VERSION 5.7 ;
BUSBITCHARS "[]" ;
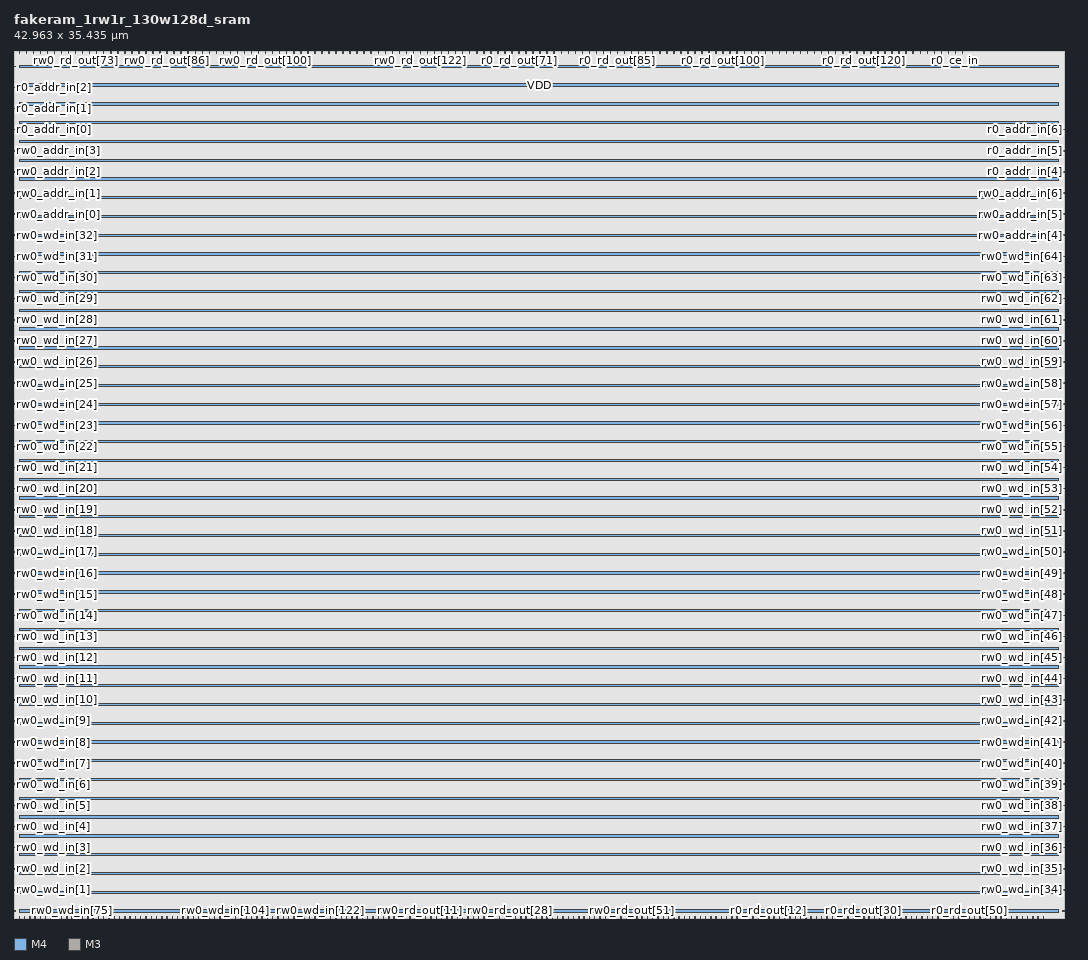
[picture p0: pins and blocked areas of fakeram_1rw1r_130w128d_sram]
MACRO fakeram_1rw1r_130w128d_sram
  FOREIGN fakeram_1rw1r_130w128d_sram 0 0 ;
  SYMMETRY X Y R90 ;
  SIZE 42.963 BY 35.435 ;
  CLASS BLOCK ;
  PIN rw0_wd_in[0]
    DIRECTION INPUT ;
    USE SIGNAL ;
    SHAPE ABUTMENT ;
    PORT
      LAYER M4 ;
      RECT 0.000 0.276 0.072 0.300 ;
    END
  END rw0_wd_in[0]
  PIN rw0_wd_in[1]
    DIRECTION INPUT ;
    USE SIGNAL ;
    SHAPE ABUTMENT ;
    PORT
      LAYER M4 ;
      RECT 0.000 1.140 0.072 1.164 ;
    END
  END rw0_wd_in[1]
  PIN rw0_wd_in[2]
    DIRECTION INPUT ;
    USE SIGNAL ;
    SHAPE ABUTMENT ;
    PORT
      LAYER M4 ;
      RECT 0.000 2.004 0.072 2.028 ;
    END
  END rw0_wd_in[2]
  PIN rw0_wd_in[3]
    DIRECTION INPUT ;
    USE SIGNAL ;
    SHAPE ABUTMENT ;
    PORT
      LAYER M4 ;
      RECT 0.000 2.868 0.072 2.892 ;
    END
  END rw0_wd_in[3]
  PIN rw0_wd_in[4]
    DIRECTION INPUT ;
    USE SIGNAL ;
    SHAPE ABUTMENT ;
    PORT
      LAYER M4 ;
      RECT 0.000 3.732 0.072 3.756 ;
    END
  END rw0_wd_in[4]
  PIN rw0_wd_in[5]
    DIRECTION INPUT ;
    USE SIGNAL ;
    SHAPE ABUTMENT ;
    PORT
      LAYER M4 ;
      RECT 0.000 4.596 0.072 4.620 ;
    END
  END rw0_wd_in[5]
  PIN rw0_wd_in[6]
    DIRECTION INPUT ;
    USE SIGNAL ;
    SHAPE ABUTMENT ;
    PORT
      LAYER M4 ;
      RECT 0.000 5.460 0.072 5.484 ;
    END
  END rw0_wd_in[6]
  PIN rw0_wd_in[7]
    DIRECTION INPUT ;
    USE SIGNAL ;
    SHAPE ABUTMENT ;
    PORT
      LAYER M4 ;
      RECT 0.000 6.324 0.072 6.348 ;
    END
  END rw0_wd_in[7]
  PIN rw0_wd_in[8]
    DIRECTION INPUT ;
    USE SIGNAL ;
    SHAPE ABUTMENT ;
    PORT
      LAYER M4 ;
      RECT 0.000 7.188 0.072 7.212 ;
    END
  END rw0_wd_in[8]
  PIN rw0_wd_in[9]
    DIRECTION INPUT ;
    USE SIGNAL ;
    SHAPE ABUTMENT ;
    PORT
      LAYER M4 ;
      RECT 0.000 8.052 0.072 8.076 ;
    END
  END rw0_wd_in[9]
  PIN rw0_wd_in[10]
    DIRECTION INPUT ;
    USE SIGNAL ;
    SHAPE ABUTMENT ;
    PORT
      LAYER M4 ;
      RECT 0.000 8.916 0.072 8.940 ;
    END
  END rw0_wd_in[10]
  PIN rw0_wd_in[11]
    DIRECTION INPUT ;
    USE SIGNAL ;
    SHAPE ABUTMENT ;
    PORT
      LAYER M4 ;
      RECT 0.000 9.780 0.072 9.804 ;
    END
  END rw0_wd_in[11]
  PIN rw0_wd_in[12]
    DIRECTION INPUT ;
    USE SIGNAL ;
    SHAPE ABUTMENT ;
    PORT
      LAYER M4 ;
      RECT 0.000 10.644 0.072 10.668 ;
    END
  END rw0_wd_in[12]
  PIN rw0_wd_in[13]
    DIRECTION INPUT ;
    USE SIGNAL ;
    SHAPE ABUTMENT ;
    PORT
      LAYER M4 ;
      RECT 0.000 11.508 0.072 11.532 ;
    END
  END rw0_wd_in[13]
  PIN rw0_wd_in[14]
    DIRECTION INPUT ;
    USE SIGNAL ;
    SHAPE ABUTMENT ;
    PORT
      LAYER M4 ;
      RECT 0.000 12.372 0.072 12.396 ;
    END
  END rw0_wd_in[14]
  PIN rw0_wd_in[15]
    DIRECTION INPUT ;
    USE SIGNAL ;
    SHAPE ABUTMENT ;
    PORT
      LAYER M4 ;
      RECT 0.000 13.236 0.072 13.260 ;
    END
  END rw0_wd_in[15]
  PIN rw0_wd_in[16]
    DIRECTION INPUT ;
    USE SIGNAL ;
    SHAPE ABUTMENT ;
    PORT
      LAYER M4 ;
      RECT 0.000 14.100 0.072 14.124 ;
    END
  END rw0_wd_in[16]
  PIN rw0_wd_in[17]
    DIRECTION INPUT ;
    USE SIGNAL ;
    SHAPE ABUTMENT ;
    PORT
      LAYER M4 ;
      RECT 0.000 14.964 0.072 14.988 ;
    END
  END rw0_wd_in[17]
  PIN rw0_wd_in[18]
    DIRECTION INPUT ;
    USE SIGNAL ;
    SHAPE ABUTMENT ;
    PORT
      LAYER M4 ;
      RECT 0.000 15.828 0.072 15.852 ;
    END
  END rw0_wd_in[18]
  PIN rw0_wd_in[19]
    DIRECTION INPUT ;
    USE SIGNAL ;
    SHAPE ABUTMENT ;
    PORT
      LAYER M4 ;
      RECT 0.000 16.692 0.072 16.716 ;
    END
  END rw0_wd_in[19]
  PIN rw0_wd_in[20]
    DIRECTION INPUT ;
    USE SIGNAL ;
    SHAPE ABUTMENT ;
    PORT
      LAYER M4 ;
      RECT 0.000 17.556 0.072 17.580 ;
    END
  END rw0_wd_in[20]
  PIN rw0_wd_in[21]
    DIRECTION INPUT ;
    USE SIGNAL ;
    SHAPE ABUTMENT ;
    PORT
      LAYER M4 ;
      RECT 0.000 18.420 0.072 18.444 ;
    END
  END rw0_wd_in[21]
  PIN rw0_wd_in[22]
    DIRECTION INPUT ;
    USE SIGNAL ;
    SHAPE ABUTMENT ;
    PORT
      LAYER M4 ;
      RECT 0.000 19.284 0.072 19.308 ;
    END
  END rw0_wd_in[22]
  PIN rw0_wd_in[23]
    DIRECTION INPUT ;
    USE SIGNAL ;
    SHAPE ABUTMENT ;
    PORT
      LAYER M4 ;
      RECT 0.000 20.148 0.072 20.172 ;
    END
  END rw0_wd_in[23]
  PIN rw0_wd_in[24]
    DIRECTION INPUT ;
    USE SIGNAL ;
    SHAPE ABUTMENT ;
    PORT
      LAYER M4 ;
      RECT 0.000 21.012 0.072 21.036 ;
    END
  END rw0_wd_in[24]
  PIN rw0_wd_in[25]
    DIRECTION INPUT ;
    USE SIGNAL ;
    SHAPE ABUTMENT ;
    PORT
      LAYER M4 ;
      RECT 0.000 21.876 0.072 21.900 ;
    END
  END rw0_wd_in[25]
  PIN rw0_wd_in[26]
    DIRECTION INPUT ;
    USE SIGNAL ;
    SHAPE ABUTMENT ;
    PORT
      LAYER M4 ;
      RECT 0.000 22.740 0.072 22.764 ;
    END
  END rw0_wd_in[26]
  PIN rw0_wd_in[27]
    DIRECTION INPUT ;
    USE SIGNAL ;
    SHAPE ABUTMENT ;
    PORT
      LAYER M4 ;
      RECT 0.000 23.604 0.072 23.628 ;
    END
  END rw0_wd_in[27]
  PIN rw0_wd_in[28]
    DIRECTION INPUT ;
    USE SIGNAL ;
    SHAPE ABUTMENT ;
    PORT
      LAYER M4 ;
      RECT 0.000 24.468 0.072 24.492 ;
    END
  END rw0_wd_in[28]
  PIN rw0_wd_in[29]
    DIRECTION INPUT ;
    USE SIGNAL ;
    SHAPE ABUTMENT ;
    PORT
      LAYER M4 ;
      RECT 0.000 25.332 0.072 25.356 ;
    END
  END rw0_wd_in[29]
  PIN rw0_wd_in[30]
    DIRECTION INPUT ;
    USE SIGNAL ;
    SHAPE ABUTMENT ;
    PORT
      LAYER M4 ;
      RECT 0.000 26.196 0.072 26.220 ;
    END
  END rw0_wd_in[30]
  PIN rw0_wd_in[31]
    DIRECTION INPUT ;
    USE SIGNAL ;
    SHAPE ABUTMENT ;
    PORT
      LAYER M4 ;
      RECT 0.000 27.060 0.072 27.084 ;
    END
  END rw0_wd_in[31]
  PIN rw0_wd_in[32]
    DIRECTION INPUT ;
    USE SIGNAL ;
    SHAPE ABUTMENT ;
    PORT
      LAYER M4 ;
      RECT 0.000 27.924 0.072 27.948 ;
    END
  END rw0_wd_in[32]
  PIN rw0_wd_in[33]
    DIRECTION INPUT ;
    USE SIGNAL ;
    SHAPE ABUTMENT ;
    PORT
      LAYER M4 ;
      RECT 42.891 0.276 42.963 0.300 ;
    END
  END rw0_wd_in[33]
  PIN rw0_wd_in[34]
    DIRECTION INPUT ;
    USE SIGNAL ;
    SHAPE ABUTMENT ;
    PORT
      LAYER M4 ;
      RECT 42.891 1.140 42.963 1.164 ;
    END
  END rw0_wd_in[34]
  PIN rw0_wd_in[35]
    DIRECTION INPUT ;
    USE SIGNAL ;
    SHAPE ABUTMENT ;
    PORT
      LAYER M4 ;
      RECT 42.891 2.004 42.963 2.028 ;
    END
  END rw0_wd_in[35]
  PIN rw0_wd_in[36]
    DIRECTION INPUT ;
    USE SIGNAL ;
    SHAPE ABUTMENT ;
    PORT
      LAYER M4 ;
      RECT 42.891 2.868 42.963 2.892 ;
    END
  END rw0_wd_in[36]
  PIN rw0_wd_in[37]
    DIRECTION INPUT ;
    USE SIGNAL ;
    SHAPE ABUTMENT ;
    PORT
      LAYER M4 ;
      RECT 42.891 3.732 42.963 3.756 ;
    END
  END rw0_wd_in[37]
  PIN rw0_wd_in[38]
    DIRECTION INPUT ;
    USE SIGNAL ;
    SHAPE ABUTMENT ;
    PORT
      LAYER M4 ;
      RECT 42.891 4.596 42.963 4.620 ;
    END
  END rw0_wd_in[38]
  PIN rw0_wd_in[39]
    DIRECTION INPUT ;
    USE SIGNAL ;
    SHAPE ABUTMENT ;
    PORT
      LAYER M4 ;
      RECT 42.891 5.460 42.963 5.484 ;
    END
  END rw0_wd_in[39]
  PIN rw0_wd_in[40]
    DIRECTION INPUT ;
    USE SIGNAL ;
    SHAPE ABUTMENT ;
    PORT
      LAYER M4 ;
      RECT 42.891 6.324 42.963 6.348 ;
    END
  END rw0_wd_in[40]
  PIN rw0_wd_in[41]
    DIRECTION INPUT ;
    USE SIGNAL ;
    SHAPE ABUTMENT ;
    PORT
      LAYER M4 ;
      RECT 42.891 7.188 42.963 7.212 ;
    END
  END rw0_wd_in[41]
  PIN rw0_wd_in[42]
    DIRECTION INPUT ;
    USE SIGNAL ;
    SHAPE ABUTMENT ;
    PORT
      LAYER M4 ;
      RECT 42.891 8.052 42.963 8.076 ;
    END
  END rw0_wd_in[42]
  PIN rw0_wd_in[43]
    DIRECTION INPUT ;
    USE SIGNAL ;
    SHAPE ABUTMENT ;
    PORT
      LAYER M4 ;
      RECT 42.891 8.916 42.963 8.940 ;
    END
  END rw0_wd_in[43]
  PIN rw0_wd_in[44]
    DIRECTION INPUT ;
    USE SIGNAL ;
    SHAPE ABUTMENT ;
    PORT
      LAYER M4 ;
      RECT 42.891 9.780 42.963 9.804 ;
    END
  END rw0_wd_in[44]
  PIN rw0_wd_in[45]
    DIRECTION INPUT ;
    USE SIGNAL ;
    SHAPE ABUTMENT ;
    PORT
      LAYER M4 ;
      RECT 42.891 10.644 42.963 10.668 ;
    END
  END rw0_wd_in[45]
  PIN rw0_wd_in[46]
    DIRECTION INPUT ;
    USE SIGNAL ;
    SHAPE ABUTMENT ;
    PORT
      LAYER M4 ;
      RECT 42.891 11.508 42.963 11.532 ;
    END
  END rw0_wd_in[46]
  PIN rw0_wd_in[47]
    DIRECTION INPUT ;
    USE SIGNAL ;
    SHAPE ABUTMENT ;
    PORT
      LAYER M4 ;
      RECT 42.891 12.372 42.963 12.396 ;
    END
  END rw0_wd_in[47]
  PIN rw0_wd_in[48]
    DIRECTION INPUT ;
    USE SIGNAL ;
    SHAPE ABUTMENT ;
    PORT
      LAYER M4 ;
      RECT 42.891 13.236 42.963 13.260 ;
    END
  END rw0_wd_in[48]
  PIN rw0_wd_in[49]
    DIRECTION INPUT ;
    USE SIGNAL ;
    SHAPE ABUTMENT ;
    PORT
      LAYER M4 ;
      RECT 42.891 14.100 42.963 14.124 ;
    END
  END rw0_wd_in[49]
  PIN rw0_wd_in[50]
    DIRECTION INPUT ;
    USE SIGNAL ;
    SHAPE ABUTMENT ;
    PORT
      LAYER M4 ;
      RECT 42.891 14.964 42.963 14.988 ;
    END
  END rw0_wd_in[50]
  PIN rw0_wd_in[51]
    DIRECTION INPUT ;
    USE SIGNAL ;
    SHAPE ABUTMENT ;
    PORT
      LAYER M4 ;
      RECT 42.891 15.828 42.963 15.852 ;
    END
  END rw0_wd_in[51]
  PIN rw0_wd_in[52]
    DIRECTION INPUT ;
    USE SIGNAL ;
    SHAPE ABUTMENT ;
    PORT
      LAYER M4 ;
      RECT 42.891 16.692 42.963 16.716 ;
    END
  END rw0_wd_in[52]
  PIN rw0_wd_in[53]
    DIRECTION INPUT ;
    USE SIGNAL ;
    SHAPE ABUTMENT ;
    PORT
      LAYER M4 ;
      RECT 42.891 17.556 42.963 17.580 ;
    END
  END rw0_wd_in[53]
  PIN rw0_wd_in[54]
    DIRECTION INPUT ;
    USE SIGNAL ;
    SHAPE ABUTMENT ;
    PORT
      LAYER M4 ;
      RECT 42.891 18.420 42.963 18.444 ;
    END
  END rw0_wd_in[54]
  PIN rw0_wd_in[55]
    DIRECTION INPUT ;
    USE SIGNAL ;
    SHAPE ABUTMENT ;
    PORT
      LAYER M4 ;
      RECT 42.891 19.284 42.963 19.308 ;
    END
  END rw0_wd_in[55]
  PIN rw0_wd_in[56]
    DIRECTION INPUT ;
    USE SIGNAL ;
    SHAPE ABUTMENT ;
    PORT
      LAYER M4 ;
      RECT 42.891 20.148 42.963 20.172 ;
    END
  END rw0_wd_in[56]
  PIN rw0_wd_in[57]
    DIRECTION INPUT ;
    USE SIGNAL ;
    SHAPE ABUTMENT ;
    PORT
      LAYER M4 ;
      RECT 42.891 21.012 42.963 21.036 ;
    END
  END rw0_wd_in[57]
  PIN rw0_wd_in[58]
    DIRECTION INPUT ;
    USE SIGNAL ;
    SHAPE ABUTMENT ;
    PORT
      LAYER M4 ;
      RECT 42.891 21.876 42.963 21.900 ;
    END
  END rw0_wd_in[58]
  PIN rw0_wd_in[59]
    DIRECTION INPUT ;
    USE SIGNAL ;
    SHAPE ABUTMENT ;
    PORT
      LAYER M4 ;
      RECT 42.891 22.740 42.963 22.764 ;
    END
  END rw0_wd_in[59]
  PIN rw0_wd_in[60]
    DIRECTION INPUT ;
    USE SIGNAL ;
    SHAPE ABUTMENT ;
    PORT
      LAYER M4 ;
      RECT 42.891 23.604 42.963 23.628 ;
    END
  END rw0_wd_in[60]
  PIN rw0_wd_in[61]
    DIRECTION INPUT ;
    USE SIGNAL ;
    SHAPE ABUTMENT ;
    PORT
      LAYER M4 ;
      RECT 42.891 24.468 42.963 24.492 ;
    END
  END rw0_wd_in[61]
  PIN rw0_wd_in[62]
    DIRECTION INPUT ;
    USE SIGNAL ;
    SHAPE ABUTMENT ;
    PORT
      LAYER M4 ;
      RECT 42.891 25.332 42.963 25.356 ;
    END
  END rw0_wd_in[62]
  PIN rw0_wd_in[63]
    DIRECTION INPUT ;
    USE SIGNAL ;
    SHAPE ABUTMENT ;
    PORT
      LAYER M4 ;
      RECT 42.891 26.196 42.963 26.220 ;
    END
  END rw0_wd_in[63]
  PIN rw0_wd_in[64]
    DIRECTION INPUT ;
    USE SIGNAL ;
    SHAPE ABUTMENT ;
    PORT
      LAYER M4 ;
      RECT 42.891 27.060 42.963 27.084 ;
    END
  END rw0_wd_in[64]
  PIN rw0_wd_in[65]
    DIRECTION OUTPUT ;
    USE SIGNAL ;
    SHAPE ABUTMENT ;
    PORT
      LAYER M3 ;
      RECT 0.207 0.000 0.225 0.054 ;
    END
  END rw0_wd_in[65]
  PIN rw0_wd_in[66]
    DIRECTION OUTPUT ;
    USE SIGNAL ;
    SHAPE ABUTMENT ;
    PORT
      LAYER M3 ;
      RECT 0.423 0.000 0.441 0.054 ;
    END
  END rw0_wd_in[66]
  PIN rw0_wd_in[67]
    DIRECTION OUTPUT ;
    USE SIGNAL ;
    SHAPE ABUTMENT ;
    PORT
      LAYER M3 ;
      RECT 0.639 0.000 0.657 0.054 ;
    END
  END rw0_wd_in[67]
  PIN rw0_wd_in[68]
    DIRECTION OUTPUT ;
    USE SIGNAL ;
    SHAPE ABUTMENT ;
    PORT
      LAYER M3 ;
      RECT 0.855 0.000 0.873 0.054 ;
    END
  END rw0_wd_in[68]
  PIN rw0_wd_in[69]
    DIRECTION OUTPUT ;
    USE SIGNAL ;
    SHAPE ABUTMENT ;
    PORT
      LAYER M3 ;
      RECT 1.071 0.000 1.089 0.054 ;
    END
  END rw0_wd_in[69]
  PIN rw0_wd_in[70]
    DIRECTION OUTPUT ;
    USE SIGNAL ;
    SHAPE ABUTMENT ;
    PORT
      LAYER M3 ;
      RECT 1.287 0.000 1.305 0.054 ;
    END
  END rw0_wd_in[70]
  PIN rw0_wd_in[71]
    DIRECTION OUTPUT ;
    USE SIGNAL ;
    SHAPE ABUTMENT ;
    PORT
      LAYER M3 ;
      RECT 1.503 0.000 1.521 0.054 ;
    END
  END rw0_wd_in[71]
  PIN rw0_wd_in[72]
    DIRECTION OUTPUT ;
    USE SIGNAL ;
    SHAPE ABUTMENT ;
    PORT
      LAYER M3 ;
      RECT 1.719 0.000 1.737 0.054 ;
    END
  END rw0_wd_in[72]
  PIN rw0_wd_in[73]
    DIRECTION OUTPUT ;
    USE SIGNAL ;
    SHAPE ABUTMENT ;
    PORT
      LAYER M3 ;
      RECT 1.935 0.000 1.953 0.054 ;
    END
  END rw0_wd_in[73]
  PIN rw0_wd_in[74]
    DIRECTION OUTPUT ;
    USE SIGNAL ;
    SHAPE ABUTMENT ;
    PORT
      LAYER M3 ;
      RECT 2.151 0.000 2.169 0.054 ;
    END
  END rw0_wd_in[74]
  PIN rw0_wd_in[75]
    DIRECTION OUTPUT ;
    USE SIGNAL ;
    SHAPE ABUTMENT ;
    PORT
      LAYER M3 ;
      RECT 2.367 0.000 2.385 0.054 ;
    END
  END rw0_wd_in[75]
  PIN rw0_wd_in[76]
    DIRECTION OUTPUT ;
    USE SIGNAL ;
    SHAPE ABUTMENT ;
    PORT
      LAYER M3 ;
      RECT 2.583 0.000 2.601 0.054 ;
    END
  END rw0_wd_in[76]
  PIN rw0_wd_in[77]
    DIRECTION OUTPUT ;
    USE SIGNAL ;
    SHAPE ABUTMENT ;
    PORT
      LAYER M3 ;
      RECT 2.799 0.000 2.817 0.054 ;
    END
  END rw0_wd_in[77]
  PIN rw0_wd_in[78]
    DIRECTION OUTPUT ;
    USE SIGNAL ;
    SHAPE ABUTMENT ;
    PORT
      LAYER M3 ;
      RECT 3.015 0.000 3.033 0.054 ;
    END
  END rw0_wd_in[78]
  PIN rw0_wd_in[79]
    DIRECTION OUTPUT ;
    USE SIGNAL ;
    SHAPE ABUTMENT ;
    PORT
      LAYER M3 ;
      RECT 3.231 0.000 3.249 0.054 ;
    END
  END rw0_wd_in[79]
  PIN rw0_wd_in[80]
    DIRECTION OUTPUT ;
    USE SIGNAL ;
    SHAPE ABUTMENT ;
    PORT
      LAYER M3 ;
      RECT 3.447 0.000 3.465 0.054 ;
    END
  END rw0_wd_in[80]
  PIN rw0_wd_in[81]
    DIRECTION OUTPUT ;
    USE SIGNAL ;
    SHAPE ABUTMENT ;
    PORT
      LAYER M3 ;
      RECT 3.663 0.000 3.681 0.054 ;
    END
  END rw0_wd_in[81]
  PIN rw0_wd_in[82]
    DIRECTION OUTPUT ;
    USE SIGNAL ;
    SHAPE ABUTMENT ;
    PORT
      LAYER M3 ;
      RECT 3.879 0.000 3.897 0.054 ;
    END
  END rw0_wd_in[82]
  PIN rw0_wd_in[83]
    DIRECTION OUTPUT ;
    USE SIGNAL ;
    SHAPE ABUTMENT ;
    PORT
      LAYER M3 ;
      RECT 4.095 0.000 4.113 0.054 ;
    END
  END rw0_wd_in[83]
  PIN rw0_wd_in[84]
    DIRECTION OUTPUT ;
    USE SIGNAL ;
    SHAPE ABUTMENT ;
    PORT
      LAYER M3 ;
      RECT 4.311 0.000 4.329 0.054 ;
    END
  END rw0_wd_in[84]
  PIN rw0_wd_in[85]
    DIRECTION OUTPUT ;
    USE SIGNAL ;
    SHAPE ABUTMENT ;
    PORT
      LAYER M3 ;
      RECT 4.527 0.000 4.545 0.054 ;
    END
  END rw0_wd_in[85]
  PIN rw0_wd_in[86]
    DIRECTION OUTPUT ;
    USE SIGNAL ;
    SHAPE ABUTMENT ;
    PORT
      LAYER M3 ;
      RECT 4.743 0.000 4.761 0.054 ;
    END
  END rw0_wd_in[86]
  PIN rw0_wd_in[87]
    DIRECTION OUTPUT ;
    USE SIGNAL ;
    SHAPE ABUTMENT ;
    PORT
      LAYER M3 ;
      RECT 4.959 0.000 4.977 0.054 ;
    END
  END rw0_wd_in[87]
  PIN rw0_wd_in[88]
    DIRECTION OUTPUT ;
    USE SIGNAL ;
    SHAPE ABUTMENT ;
    PORT
      LAYER M3 ;
      RECT 5.175 0.000 5.193 0.054 ;
    END
  END rw0_wd_in[88]
  PIN rw0_wd_in[89]
    DIRECTION OUTPUT ;
    USE SIGNAL ;
    SHAPE ABUTMENT ;
    PORT
      LAYER M3 ;
      RECT 5.391 0.000 5.409 0.054 ;
    END
  END rw0_wd_in[89]
  PIN rw0_wd_in[90]
    DIRECTION OUTPUT ;
    USE SIGNAL ;
    SHAPE ABUTMENT ;
    PORT
      LAYER M3 ;
      RECT 5.607 0.000 5.625 0.054 ;
    END
  END rw0_wd_in[90]
  PIN rw0_wd_in[91]
    DIRECTION OUTPUT ;
    USE SIGNAL ;
    SHAPE ABUTMENT ;
    PORT
      LAYER M3 ;
      RECT 5.823 0.000 5.841 0.054 ;
    END
  END rw0_wd_in[91]
  PIN rw0_wd_in[92]
    DIRECTION OUTPUT ;
    USE SIGNAL ;
    SHAPE ABUTMENT ;
    PORT
      LAYER M3 ;
      RECT 6.039 0.000 6.057 0.054 ;
    END
  END rw0_wd_in[92]
  PIN rw0_wd_in[93]
    DIRECTION OUTPUT ;
    USE SIGNAL ;
    SHAPE ABUTMENT ;
    PORT
      LAYER M3 ;
      RECT 6.255 0.000 6.273 0.054 ;
    END
  END rw0_wd_in[93]
  PIN rw0_wd_in[94]
    DIRECTION OUTPUT ;
    USE SIGNAL ;
    SHAPE ABUTMENT ;
    PORT
      LAYER M3 ;
      RECT 6.471 0.000 6.489 0.054 ;
    END
  END rw0_wd_in[94]
  PIN rw0_wd_in[95]
    DIRECTION OUTPUT ;
    USE SIGNAL ;
    SHAPE ABUTMENT ;
    PORT
      LAYER M3 ;
      RECT 6.687 0.000 6.705 0.054 ;
    END
  END rw0_wd_in[95]
  PIN rw0_wd_in[96]
    DIRECTION OUTPUT ;
    USE SIGNAL ;
    SHAPE ABUTMENT ;
    PORT
      LAYER M3 ;
      RECT 6.903 0.000 6.921 0.054 ;
    END
  END rw0_wd_in[96]
  PIN rw0_wd_in[97]
    DIRECTION OUTPUT ;
    USE SIGNAL ;
    SHAPE ABUTMENT ;
    PORT
      LAYER M3 ;
      RECT 7.119 0.000 7.137 0.054 ;
    END
  END rw0_wd_in[97]
  PIN rw0_wd_in[98]
    DIRECTION OUTPUT ;
    USE SIGNAL ;
    SHAPE ABUTMENT ;
    PORT
      LAYER M3 ;
      RECT 7.335 0.000 7.353 0.054 ;
    END
  END rw0_wd_in[98]
  PIN rw0_wd_in[99]
    DIRECTION OUTPUT ;
    USE SIGNAL ;
    SHAPE ABUTMENT ;
    PORT
      LAYER M3 ;
      RECT 7.551 0.000 7.569 0.054 ;
    END
  END rw0_wd_in[99]
  PIN rw0_wd_in[100]
    DIRECTION OUTPUT ;
    USE SIGNAL ;
    SHAPE ABUTMENT ;
    PORT
      LAYER M3 ;
      RECT 7.767 0.000 7.785 0.054 ;
    END
  END rw0_wd_in[100]
  PIN rw0_wd_in[101]
    DIRECTION OUTPUT ;
    USE SIGNAL ;
    SHAPE ABUTMENT ;
    PORT
      LAYER M3 ;
      RECT 7.983 0.000 8.001 0.054 ;
    END
  END rw0_wd_in[101]
  PIN rw0_wd_in[102]
    DIRECTION OUTPUT ;
    USE SIGNAL ;
    SHAPE ABUTMENT ;
    PORT
      LAYER M3 ;
      RECT 8.199 0.000 8.217 0.054 ;
    END
  END rw0_wd_in[102]
  PIN rw0_wd_in[103]
    DIRECTION OUTPUT ;
    USE SIGNAL ;
    SHAPE ABUTMENT ;
    PORT
      LAYER M3 ;
      RECT 8.415 0.000 8.433 0.054 ;
    END
  END rw0_wd_in[103]
  PIN rw0_wd_in[104]
    DIRECTION OUTPUT ;
    USE SIGNAL ;
    SHAPE ABUTMENT ;
    PORT
      LAYER M3 ;
      RECT 8.631 0.000 8.649 0.054 ;
    END
  END rw0_wd_in[104]
  PIN rw0_wd_in[105]
    DIRECTION OUTPUT ;
    USE SIGNAL ;
    SHAPE ABUTMENT ;
    PORT
      LAYER M3 ;
      RECT 8.847 0.000 8.865 0.054 ;
    END
  END rw0_wd_in[105]
  PIN rw0_wd_in[106]
    DIRECTION OUTPUT ;
    USE SIGNAL ;
    SHAPE ABUTMENT ;
    PORT
      LAYER M3 ;
      RECT 9.063 0.000 9.081 0.054 ;
    END
  END rw0_wd_in[106]
  PIN rw0_wd_in[107]
    DIRECTION OUTPUT ;
    USE SIGNAL ;
    SHAPE ABUTMENT ;
    PORT
      LAYER M3 ;
      RECT 9.279 0.000 9.297 0.054 ;
    END
  END rw0_wd_in[107]
  PIN rw0_wd_in[108]
    DIRECTION OUTPUT ;
    USE SIGNAL ;
    SHAPE ABUTMENT ;
    PORT
      LAYER M3 ;
      RECT 9.495 0.000 9.513 0.054 ;
    END
  END rw0_wd_in[108]
  PIN rw0_wd_in[109]
    DIRECTION OUTPUT ;
    USE SIGNAL ;
    SHAPE ABUTMENT ;
    PORT
      LAYER M3 ;
      RECT 9.711 0.000 9.729 0.054 ;
    END
  END rw0_wd_in[109]
  PIN rw0_wd_in[110]
    DIRECTION OUTPUT ;
    USE SIGNAL ;
    SHAPE ABUTMENT ;
    PORT
      LAYER M3 ;
      RECT 9.927 0.000 9.945 0.054 ;
    END
  END rw0_wd_in[110]
  PIN rw0_wd_in[111]
    DIRECTION OUTPUT ;
    USE SIGNAL ;
    SHAPE ABUTMENT ;
    PORT
      LAYER M3 ;
      RECT 10.143 0.000 10.161 0.054 ;
    END
  END rw0_wd_in[111]
  PIN rw0_wd_in[112]
    DIRECTION OUTPUT ;
    USE SIGNAL ;
    SHAPE ABUTMENT ;
    PORT
      LAYER M3 ;
      RECT 10.359 0.000 10.377 0.054 ;
    END
  END rw0_wd_in[112]
  PIN rw0_wd_in[113]
    DIRECTION OUTPUT ;
    USE SIGNAL ;
    SHAPE ABUTMENT ;
    PORT
      LAYER M3 ;
      RECT 10.575 0.000 10.593 0.054 ;
    END
  END rw0_wd_in[113]
  PIN rw0_wd_in[114]
    DIRECTION OUTPUT ;
    USE SIGNAL ;
    SHAPE ABUTMENT ;
    PORT
      LAYER M3 ;
      RECT 10.791 0.000 10.809 0.054 ;
    END
  END rw0_wd_in[114]
  PIN rw0_wd_in[115]
    DIRECTION OUTPUT ;
    USE SIGNAL ;
    SHAPE ABUTMENT ;
    PORT
      LAYER M3 ;
      RECT 11.007 0.000 11.025 0.054 ;
    END
  END rw0_wd_in[115]
  PIN rw0_wd_in[116]
    DIRECTION OUTPUT ;
    USE SIGNAL ;
    SHAPE ABUTMENT ;
    PORT
      LAYER M3 ;
      RECT 11.223 0.000 11.241 0.054 ;
    END
  END rw0_wd_in[116]
  PIN rw0_wd_in[117]
    DIRECTION OUTPUT ;
    USE SIGNAL ;
    SHAPE ABUTMENT ;
    PORT
      LAYER M3 ;
      RECT 11.439 0.000 11.457 0.054 ;
    END
  END rw0_wd_in[117]
  PIN rw0_wd_in[118]
    DIRECTION OUTPUT ;
    USE SIGNAL ;
    SHAPE ABUTMENT ;
    PORT
      LAYER M3 ;
      RECT 11.655 0.000 11.673 0.054 ;
    END
  END rw0_wd_in[118]
  PIN rw0_wd_in[119]
    DIRECTION OUTPUT ;
    USE SIGNAL ;
    SHAPE ABUTMENT ;
    PORT
      LAYER M3 ;
      RECT 11.871 0.000 11.889 0.054 ;
    END
  END rw0_wd_in[119]
  PIN rw0_wd_in[120]
    DIRECTION OUTPUT ;
    USE SIGNAL ;
    SHAPE ABUTMENT ;
    PORT
      LAYER M3 ;
      RECT 12.087 0.000 12.105 0.054 ;
    END
  END rw0_wd_in[120]
  PIN rw0_wd_in[121]
    DIRECTION OUTPUT ;
    USE SIGNAL ;
    SHAPE ABUTMENT ;
    PORT
      LAYER M3 ;
      RECT 12.303 0.000 12.321 0.054 ;
    END
  END rw0_wd_in[121]
  PIN rw0_wd_in[122]
    DIRECTION OUTPUT ;
    USE SIGNAL ;
    SHAPE ABUTMENT ;
    PORT
      LAYER M3 ;
      RECT 12.519 0.000 12.537 0.054 ;
    END
  END rw0_wd_in[122]
  PIN rw0_wd_in[123]
    DIRECTION OUTPUT ;
    USE SIGNAL ;
    SHAPE ABUTMENT ;
    PORT
      LAYER M3 ;
      RECT 12.735 0.000 12.753 0.054 ;
    END
  END rw0_wd_in[123]
  PIN rw0_wd_in[124]
    DIRECTION OUTPUT ;
    USE SIGNAL ;
    SHAPE ABUTMENT ;
    PORT
      LAYER M3 ;
      RECT 12.951 0.000 12.969 0.054 ;
    END
  END rw0_wd_in[124]
  PIN rw0_wd_in[125]
    DIRECTION OUTPUT ;
    USE SIGNAL ;
    SHAPE ABUTMENT ;
    PORT
      LAYER M3 ;
      RECT 13.167 0.000 13.185 0.054 ;
    END
  END rw0_wd_in[125]
  PIN rw0_wd_in[126]
    DIRECTION OUTPUT ;
    USE SIGNAL ;
    SHAPE ABUTMENT ;
    PORT
      LAYER M3 ;
      RECT 13.383 0.000 13.401 0.054 ;
    END
  END rw0_wd_in[126]
  PIN rw0_wd_in[127]
    DIRECTION OUTPUT ;
    USE SIGNAL ;
    SHAPE ABUTMENT ;
    PORT
      LAYER M3 ;
      RECT 13.599 0.000 13.617 0.054 ;
    END
  END rw0_wd_in[127]
  PIN rw0_wd_in[128]
    DIRECTION OUTPUT ;
    USE SIGNAL ;
    SHAPE ABUTMENT ;
    PORT
      LAYER M3 ;
      RECT 13.815 0.000 13.833 0.054 ;
    END
  END rw0_wd_in[128]
  PIN rw0_wd_in[129]
    DIRECTION OUTPUT ;
    USE SIGNAL ;
    SHAPE ABUTMENT ;
    PORT
      LAYER M3 ;
      RECT 14.031 0.000 14.049 0.054 ;
    END
  END rw0_wd_in[129]
  PIN rw0_rd_out[0]
    DIRECTION OUTPUT ;
    USE SIGNAL ;
    SHAPE ABUTMENT ;
    PORT
      LAYER M3 ;
      RECT 14.247 0.000 14.265 0.054 ;
    END
  END rw0_rd_out[0]
  PIN rw0_rd_out[1]
    DIRECTION OUTPUT ;
    USE SIGNAL ;
    SHAPE ABUTMENT ;
    PORT
      LAYER M3 ;
      RECT 14.463 0.000 14.481 0.054 ;
    END
  END rw0_rd_out[1]
  PIN rw0_rd_out[2]
    DIRECTION OUTPUT ;
    USE SIGNAL ;
    SHAPE ABUTMENT ;
    PORT
      LAYER M3 ;
      RECT 14.679 0.000 14.697 0.054 ;
    END
  END rw0_rd_out[2]
  PIN rw0_rd_out[3]
    DIRECTION OUTPUT ;
    USE SIGNAL ;
    SHAPE ABUTMENT ;
    PORT
      LAYER M3 ;
      RECT 14.895 0.000 14.913 0.054 ;
    END
  END rw0_rd_out[3]
  PIN rw0_rd_out[4]
    DIRECTION OUTPUT ;
    USE SIGNAL ;
    SHAPE ABUTMENT ;
    PORT
      LAYER M3 ;
      RECT 15.111 0.000 15.129 0.054 ;
    END
  END rw0_rd_out[4]
  PIN rw0_rd_out[5]
    DIRECTION OUTPUT ;
    USE SIGNAL ;
    SHAPE ABUTMENT ;
    PORT
      LAYER M3 ;
      RECT 15.327 0.000 15.345 0.054 ;
    END
  END rw0_rd_out[5]
  PIN rw0_rd_out[6]
    DIRECTION OUTPUT ;
    USE SIGNAL ;
    SHAPE ABUTMENT ;
    PORT
      LAYER M3 ;
      RECT 15.543 0.000 15.561 0.054 ;
    END
  END rw0_rd_out[6]
  PIN rw0_rd_out[7]
    DIRECTION OUTPUT ;
    USE SIGNAL ;
    SHAPE ABUTMENT ;
    PORT
      LAYER M3 ;
      RECT 15.759 0.000 15.777 0.054 ;
    END
  END rw0_rd_out[7]
  PIN rw0_rd_out[8]
    DIRECTION OUTPUT ;
    USE SIGNAL ;
    SHAPE ABUTMENT ;
    PORT
      LAYER M3 ;
      RECT 15.975 0.000 15.993 0.054 ;
    END
  END rw0_rd_out[8]
  PIN rw0_rd_out[9]
    DIRECTION OUTPUT ;
    USE SIGNAL ;
    SHAPE ABUTMENT ;
    PORT
      LAYER M3 ;
      RECT 16.191 0.000 16.209 0.054 ;
    END
  END rw0_rd_out[9]
  PIN rw0_rd_out[10]
    DIRECTION OUTPUT ;
    USE SIGNAL ;
    SHAPE ABUTMENT ;
    PORT
      LAYER M3 ;
      RECT 16.407 0.000 16.425 0.054 ;
    END
  END rw0_rd_out[10]
  PIN rw0_rd_out[11]
    DIRECTION OUTPUT ;
    USE SIGNAL ;
    SHAPE ABUTMENT ;
    PORT
      LAYER M3 ;
      RECT 16.623 0.000 16.641 0.054 ;
    END
  END rw0_rd_out[11]
  PIN rw0_rd_out[12]
    DIRECTION OUTPUT ;
    USE SIGNAL ;
    SHAPE ABUTMENT ;
    PORT
      LAYER M3 ;
      RECT 16.839 0.000 16.857 0.054 ;
    END
  END rw0_rd_out[12]
  PIN rw0_rd_out[13]
    DIRECTION OUTPUT ;
    USE SIGNAL ;
    SHAPE ABUTMENT ;
    PORT
      LAYER M3 ;
      RECT 17.055 0.000 17.073 0.054 ;
    END
  END rw0_rd_out[13]
  PIN rw0_rd_out[14]
    DIRECTION OUTPUT ;
    USE SIGNAL ;
    SHAPE ABUTMENT ;
    PORT
      LAYER M3 ;
      RECT 17.271 0.000 17.289 0.054 ;
    END
  END rw0_rd_out[14]
  PIN rw0_rd_out[15]
    DIRECTION OUTPUT ;
    USE SIGNAL ;
    SHAPE ABUTMENT ;
    PORT
      LAYER M3 ;
      RECT 17.487 0.000 17.505 0.054 ;
    END
  END rw0_rd_out[15]
  PIN rw0_rd_out[16]
    DIRECTION OUTPUT ;
    USE SIGNAL ;
    SHAPE ABUTMENT ;
    PORT
      LAYER M3 ;
      RECT 17.703 0.000 17.721 0.054 ;
    END
  END rw0_rd_out[16]
  PIN rw0_rd_out[17]
    DIRECTION OUTPUT ;
    USE SIGNAL ;
    SHAPE ABUTMENT ;
    PORT
      LAYER M3 ;
      RECT 17.919 0.000 17.937 0.054 ;
    END
  END rw0_rd_out[17]
  PIN rw0_rd_out[18]
    DIRECTION OUTPUT ;
    USE SIGNAL ;
    SHAPE ABUTMENT ;
    PORT
      LAYER M3 ;
      RECT 18.135 0.000 18.153 0.054 ;
    END
  END rw0_rd_out[18]
  PIN rw0_rd_out[19]
    DIRECTION OUTPUT ;
    USE SIGNAL ;
    SHAPE ABUTMENT ;
    PORT
      LAYER M3 ;
      RECT 18.351 0.000 18.369 0.054 ;
    END
  END rw0_rd_out[19]
  PIN rw0_rd_out[20]
    DIRECTION OUTPUT ;
    USE SIGNAL ;
    SHAPE ABUTMENT ;
    PORT
      LAYER M3 ;
      RECT 18.567 0.000 18.585 0.054 ;
    END
  END rw0_rd_out[20]
  PIN rw0_rd_out[21]
    DIRECTION OUTPUT ;
    USE SIGNAL ;
    SHAPE ABUTMENT ;
    PORT
      LAYER M3 ;
      RECT 18.783 0.000 18.801 0.054 ;
    END
  END rw0_rd_out[21]
  PIN rw0_rd_out[22]
    DIRECTION OUTPUT ;
    USE SIGNAL ;
    SHAPE ABUTMENT ;
    PORT
      LAYER M3 ;
      RECT 18.999 0.000 19.017 0.054 ;
    END
  END rw0_rd_out[22]
  PIN rw0_rd_out[23]
    DIRECTION OUTPUT ;
    USE SIGNAL ;
    SHAPE ABUTMENT ;
    PORT
      LAYER M3 ;
      RECT 19.215 0.000 19.233 0.054 ;
    END
  END rw0_rd_out[23]
  PIN rw0_rd_out[24]
    DIRECTION OUTPUT ;
    USE SIGNAL ;
    SHAPE ABUTMENT ;
    PORT
      LAYER M3 ;
      RECT 19.431 0.000 19.449 0.054 ;
    END
  END rw0_rd_out[24]
  PIN rw0_rd_out[25]
    DIRECTION OUTPUT ;
    USE SIGNAL ;
    SHAPE ABUTMENT ;
    PORT
      LAYER M3 ;
      RECT 19.647 0.000 19.665 0.054 ;
    END
  END rw0_rd_out[25]
  PIN rw0_rd_out[26]
    DIRECTION OUTPUT ;
    USE SIGNAL ;
    SHAPE ABUTMENT ;
    PORT
      LAYER M3 ;
      RECT 19.863 0.000 19.881 0.054 ;
    END
  END rw0_rd_out[26]
  PIN rw0_rd_out[27]
    DIRECTION OUTPUT ;
    USE SIGNAL ;
    SHAPE ABUTMENT ;
    PORT
      LAYER M3 ;
      RECT 20.079 0.000 20.097 0.054 ;
    END
  END rw0_rd_out[27]
  PIN rw0_rd_out[28]
    DIRECTION OUTPUT ;
    USE SIGNAL ;
    SHAPE ABUTMENT ;
    PORT
      LAYER M3 ;
      RECT 20.295 0.000 20.313 0.054 ;
    END
  END rw0_rd_out[28]
  PIN rw0_rd_out[29]
    DIRECTION OUTPUT ;
    USE SIGNAL ;
    SHAPE ABUTMENT ;
    PORT
      LAYER M3 ;
      RECT 20.511 0.000 20.529 0.054 ;
    END
  END rw0_rd_out[29]
  PIN rw0_rd_out[30]
    DIRECTION OUTPUT ;
    USE SIGNAL ;
    SHAPE ABUTMENT ;
    PORT
      LAYER M3 ;
      RECT 20.727 0.000 20.745 0.054 ;
    END
  END rw0_rd_out[30]
  PIN rw0_rd_out[31]
    DIRECTION OUTPUT ;
    USE SIGNAL ;
    SHAPE ABUTMENT ;
    PORT
      LAYER M3 ;
      RECT 20.943 0.000 20.961 0.054 ;
    END
  END rw0_rd_out[31]
  PIN rw0_rd_out[32]
    DIRECTION OUTPUT ;
    USE SIGNAL ;
    SHAPE ABUTMENT ;
    PORT
      LAYER M3 ;
      RECT 21.159 0.000 21.177 0.054 ;
    END
  END rw0_rd_out[32]
  PIN rw0_rd_out[33]
    DIRECTION OUTPUT ;
    USE SIGNAL ;
    SHAPE ABUTMENT ;
    PORT
      LAYER M3 ;
      RECT 21.375 0.000 21.393 0.054 ;
    END
  END rw0_rd_out[33]
  PIN rw0_rd_out[34]
    DIRECTION OUTPUT ;
    USE SIGNAL ;
    SHAPE ABUTMENT ;
    PORT
      LAYER M3 ;
      RECT 21.591 0.000 21.609 0.054 ;
    END
  END rw0_rd_out[34]
  PIN rw0_rd_out[35]
    DIRECTION OUTPUT ;
    USE SIGNAL ;
    SHAPE ABUTMENT ;
    PORT
      LAYER M3 ;
      RECT 21.807 0.000 21.825 0.054 ;
    END
  END rw0_rd_out[35]
  PIN rw0_rd_out[36]
    DIRECTION OUTPUT ;
    USE SIGNAL ;
    SHAPE ABUTMENT ;
    PORT
      LAYER M3 ;
      RECT 22.023 0.000 22.041 0.054 ;
    END
  END rw0_rd_out[36]
  PIN rw0_rd_out[37]
    DIRECTION OUTPUT ;
    USE SIGNAL ;
    SHAPE ABUTMENT ;
    PORT
      LAYER M3 ;
      RECT 22.239 0.000 22.257 0.054 ;
    END
  END rw0_rd_out[37]
  PIN rw0_rd_out[38]
    DIRECTION OUTPUT ;
    USE SIGNAL ;
    SHAPE ABUTMENT ;
    PORT
      LAYER M3 ;
      RECT 22.455 0.000 22.473 0.054 ;
    END
  END rw0_rd_out[38]
  PIN rw0_rd_out[39]
    DIRECTION OUTPUT ;
    USE SIGNAL ;
    SHAPE ABUTMENT ;
    PORT
      LAYER M3 ;
      RECT 22.671 0.000 22.689 0.054 ;
    END
  END rw0_rd_out[39]
  PIN rw0_rd_out[40]
    DIRECTION OUTPUT ;
    USE SIGNAL ;
    SHAPE ABUTMENT ;
    PORT
      LAYER M3 ;
      RECT 22.887 0.000 22.905 0.054 ;
    END
  END rw0_rd_out[40]
  PIN rw0_rd_out[41]
    DIRECTION OUTPUT ;
    USE SIGNAL ;
    SHAPE ABUTMENT ;
    PORT
      LAYER M3 ;
      RECT 23.103 0.000 23.121 0.054 ;
    END
  END rw0_rd_out[41]
  PIN rw0_rd_out[42]
    DIRECTION OUTPUT ;
    USE SIGNAL ;
    SHAPE ABUTMENT ;
    PORT
      LAYER M3 ;
      RECT 23.319 0.000 23.337 0.054 ;
    END
  END rw0_rd_out[42]
  PIN rw0_rd_out[43]
    DIRECTION OUTPUT ;
    USE SIGNAL ;
    SHAPE ABUTMENT ;
    PORT
      LAYER M3 ;
      RECT 23.535 0.000 23.553 0.054 ;
    END
  END rw0_rd_out[43]
  PIN rw0_rd_out[44]
    DIRECTION OUTPUT ;
    USE SIGNAL ;
    SHAPE ABUTMENT ;
    PORT
      LAYER M3 ;
      RECT 23.751 0.000 23.769 0.054 ;
    END
  END rw0_rd_out[44]
  PIN rw0_rd_out[45]
    DIRECTION OUTPUT ;
    USE SIGNAL ;
    SHAPE ABUTMENT ;
    PORT
      LAYER M3 ;
      RECT 23.967 0.000 23.985 0.054 ;
    END
  END rw0_rd_out[45]
  PIN rw0_rd_out[46]
    DIRECTION OUTPUT ;
    USE SIGNAL ;
    SHAPE ABUTMENT ;
    PORT
      LAYER M3 ;
      RECT 24.183 0.000 24.201 0.054 ;
    END
  END rw0_rd_out[46]
  PIN rw0_rd_out[47]
    DIRECTION OUTPUT ;
    USE SIGNAL ;
    SHAPE ABUTMENT ;
    PORT
      LAYER M3 ;
      RECT 24.399 0.000 24.417 0.054 ;
    END
  END rw0_rd_out[47]
  PIN rw0_rd_out[48]
    DIRECTION OUTPUT ;
    USE SIGNAL ;
    SHAPE ABUTMENT ;
    PORT
      LAYER M3 ;
      RECT 24.615 0.000 24.633 0.054 ;
    END
  END rw0_rd_out[48]
  PIN rw0_rd_out[49]
    DIRECTION OUTPUT ;
    USE SIGNAL ;
    SHAPE ABUTMENT ;
    PORT
      LAYER M3 ;
      RECT 24.831 0.000 24.849 0.054 ;
    END
  END rw0_rd_out[49]
  PIN rw0_rd_out[50]
    DIRECTION OUTPUT ;
    USE SIGNAL ;
    SHAPE ABUTMENT ;
    PORT
      LAYER M3 ;
      RECT 25.047 0.000 25.065 0.054 ;
    END
  END rw0_rd_out[50]
  PIN rw0_rd_out[51]
    DIRECTION OUTPUT ;
    USE SIGNAL ;
    SHAPE ABUTMENT ;
    PORT
      LAYER M3 ;
      RECT 25.263 0.000 25.281 0.054 ;
    END
  END rw0_rd_out[51]
  PIN rw0_rd_out[52]
    DIRECTION OUTPUT ;
    USE SIGNAL ;
    SHAPE ABUTMENT ;
    PORT
      LAYER M3 ;
      RECT 25.479 0.000 25.497 0.054 ;
    END
  END rw0_rd_out[52]
  PIN rw0_rd_out[53]
    DIRECTION OUTPUT ;
    USE SIGNAL ;
    SHAPE ABUTMENT ;
    PORT
      LAYER M3 ;
      RECT 25.695 0.000 25.713 0.054 ;
    END
  END rw0_rd_out[53]
  PIN rw0_rd_out[54]
    DIRECTION OUTPUT ;
    USE SIGNAL ;
    SHAPE ABUTMENT ;
    PORT
      LAYER M3 ;
      RECT 25.911 0.000 25.929 0.054 ;
    END
  END rw0_rd_out[54]
  PIN rw0_rd_out[55]
    DIRECTION OUTPUT ;
    USE SIGNAL ;
    SHAPE ABUTMENT ;
    PORT
      LAYER M3 ;
      RECT 26.127 0.000 26.145 0.054 ;
    END
  END rw0_rd_out[55]
  PIN rw0_rd_out[56]
    DIRECTION OUTPUT ;
    USE SIGNAL ;
    SHAPE ABUTMENT ;
    PORT
      LAYER M3 ;
      RECT 26.343 0.000 26.361 0.054 ;
    END
  END rw0_rd_out[56]
  PIN rw0_rd_out[57]
    DIRECTION OUTPUT ;
    USE SIGNAL ;
    SHAPE ABUTMENT ;
    PORT
      LAYER M3 ;
      RECT 26.559 0.000 26.577 0.054 ;
    END
  END rw0_rd_out[57]
  PIN rw0_rd_out[58]
    DIRECTION OUTPUT ;
    USE SIGNAL ;
    SHAPE ABUTMENT ;
    PORT
      LAYER M3 ;
      RECT 26.775 0.000 26.793 0.054 ;
    END
  END rw0_rd_out[58]
  PIN rw0_rd_out[59]
    DIRECTION OUTPUT ;
    USE SIGNAL ;
    SHAPE ABUTMENT ;
    PORT
      LAYER M3 ;
      RECT 26.991 0.000 27.009 0.054 ;
    END
  END rw0_rd_out[59]
  PIN rw0_rd_out[60]
    DIRECTION OUTPUT ;
    USE SIGNAL ;
    SHAPE ABUTMENT ;
    PORT
      LAYER M3 ;
      RECT 27.207 0.000 27.225 0.054 ;
    END
  END rw0_rd_out[60]
  PIN rw0_rd_out[61]
    DIRECTION OUTPUT ;
    USE SIGNAL ;
    SHAPE ABUTMENT ;
    PORT
      LAYER M3 ;
      RECT 27.423 0.000 27.441 0.054 ;
    END
  END rw0_rd_out[61]
  PIN rw0_rd_out[62]
    DIRECTION OUTPUT ;
    USE SIGNAL ;
    SHAPE ABUTMENT ;
    PORT
      LAYER M3 ;
      RECT 27.639 0.000 27.657 0.054 ;
    END
  END rw0_rd_out[62]
  PIN rw0_rd_out[63]
    DIRECTION OUTPUT ;
    USE SIGNAL ;
    SHAPE ABUTMENT ;
    PORT
      LAYER M3 ;
      RECT 27.855 0.000 27.873 0.054 ;
    END
  END rw0_rd_out[63]
  PIN rw0_rd_out[64]
    DIRECTION OUTPUT ;
    USE SIGNAL ;
    SHAPE ABUTMENT ;
    PORT
      LAYER M3 ;
      RECT 28.071 0.000 28.089 0.054 ;
    END
  END rw0_rd_out[64]
  PIN rw0_rd_out[65]
    DIRECTION OUTPUT ;
    USE SIGNAL ;
    SHAPE ABUTMENT ;
    PORT
      LAYER M3 ;
      RECT 0.207 35.381 0.225 35.435 ;
    END
  END rw0_rd_out[65]
  PIN rw0_rd_out[66]
    DIRECTION OUTPUT ;
    USE SIGNAL ;
    SHAPE ABUTMENT ;
    PORT
      LAYER M3 ;
      RECT 0.495 35.381 0.513 35.435 ;
    END
  END rw0_rd_out[66]
  PIN rw0_rd_out[67]
    DIRECTION OUTPUT ;
    USE SIGNAL ;
    SHAPE ABUTMENT ;
    PORT
      LAYER M3 ;
      RECT 0.783 35.381 0.801 35.435 ;
    END
  END rw0_rd_out[67]
  PIN rw0_rd_out[68]
    DIRECTION OUTPUT ;
    USE SIGNAL ;
    SHAPE ABUTMENT ;
    PORT
      LAYER M3 ;
      RECT 1.071 35.381 1.089 35.435 ;
    END
  END rw0_rd_out[68]
  PIN rw0_rd_out[69]
    DIRECTION OUTPUT ;
    USE SIGNAL ;
    SHAPE ABUTMENT ;
    PORT
      LAYER M3 ;
      RECT 1.359 35.381 1.377 35.435 ;
    END
  END rw0_rd_out[69]
  PIN rw0_rd_out[70]
    DIRECTION OUTPUT ;
    USE SIGNAL ;
    SHAPE ABUTMENT ;
    PORT
      LAYER M3 ;
      RECT 1.647 35.381 1.665 35.435 ;
    END
  END rw0_rd_out[70]
  PIN rw0_rd_out[71]
    DIRECTION OUTPUT ;
    USE SIGNAL ;
    SHAPE ABUTMENT ;
    PORT
      LAYER M3 ;
      RECT 1.935 35.381 1.953 35.435 ;
    END
  END rw0_rd_out[71]
  PIN rw0_rd_out[72]
    DIRECTION OUTPUT ;
    USE SIGNAL ;
    SHAPE ABUTMENT ;
    PORT
      LAYER M3 ;
      RECT 2.223 35.381 2.241 35.435 ;
    END
  END rw0_rd_out[72]
  PIN rw0_rd_out[73]
    DIRECTION OUTPUT ;
    USE SIGNAL ;
    SHAPE ABUTMENT ;
    PORT
      LAYER M3 ;
      RECT 2.511 35.381 2.529 35.435 ;
    END
  END rw0_rd_out[73]
  PIN rw0_rd_out[74]
    DIRECTION OUTPUT ;
    USE SIGNAL ;
    SHAPE ABUTMENT ;
    PORT
      LAYER M3 ;
      RECT 2.799 35.381 2.817 35.435 ;
    END
  END rw0_rd_out[74]
  PIN rw0_rd_out[75]
    DIRECTION OUTPUT ;
    USE SIGNAL ;
    SHAPE ABUTMENT ;
    PORT
      LAYER M3 ;
      RECT 3.087 35.381 3.105 35.435 ;
    END
  END rw0_rd_out[75]
  PIN rw0_rd_out[76]
    DIRECTION OUTPUT ;
    USE SIGNAL ;
    SHAPE ABUTMENT ;
    PORT
      LAYER M3 ;
      RECT 3.375 35.381 3.393 35.435 ;
    END
  END rw0_rd_out[76]
  PIN rw0_rd_out[77]
    DIRECTION OUTPUT ;
    USE SIGNAL ;
    SHAPE ABUTMENT ;
    PORT
      LAYER M3 ;
      RECT 3.663 35.381 3.681 35.435 ;
    END
  END rw0_rd_out[77]
  PIN rw0_rd_out[78]
    DIRECTION OUTPUT ;
    USE SIGNAL ;
    SHAPE ABUTMENT ;
    PORT
      LAYER M3 ;
      RECT 3.951 35.381 3.969 35.435 ;
    END
  END rw0_rd_out[78]
  PIN rw0_rd_out[79]
    DIRECTION OUTPUT ;
    USE SIGNAL ;
    SHAPE ABUTMENT ;
    PORT
      LAYER M3 ;
      RECT 4.239 35.381 4.257 35.435 ;
    END
  END rw0_rd_out[79]
  PIN rw0_rd_out[80]
    DIRECTION OUTPUT ;
    USE SIGNAL ;
    SHAPE ABUTMENT ;
    PORT
      LAYER M3 ;
      RECT 4.527 35.381 4.545 35.435 ;
    END
  END rw0_rd_out[80]
  PIN rw0_rd_out[81]
    DIRECTION OUTPUT ;
    USE SIGNAL ;
    SHAPE ABUTMENT ;
    PORT
      LAYER M3 ;
      RECT 4.815 35.381 4.833 35.435 ;
    END
  END rw0_rd_out[81]
  PIN rw0_rd_out[82]
    DIRECTION OUTPUT ;
    USE SIGNAL ;
    SHAPE ABUTMENT ;
    PORT
      LAYER M3 ;
      RECT 5.103 35.381 5.121 35.435 ;
    END
  END rw0_rd_out[82]
  PIN rw0_rd_out[83]
    DIRECTION OUTPUT ;
    USE SIGNAL ;
    SHAPE ABUTMENT ;
    PORT
      LAYER M3 ;
      RECT 5.391 35.381 5.409 35.435 ;
    END
  END rw0_rd_out[83]
  PIN rw0_rd_out[84]
    DIRECTION OUTPUT ;
    USE SIGNAL ;
    SHAPE ABUTMENT ;
    PORT
      LAYER M3 ;
      RECT 5.679 35.381 5.697 35.435 ;
    END
  END rw0_rd_out[84]
  PIN rw0_rd_out[85]
    DIRECTION OUTPUT ;
    USE SIGNAL ;
    SHAPE ABUTMENT ;
    PORT
      LAYER M3 ;
      RECT 5.967 35.381 5.985 35.435 ;
    END
  END rw0_rd_out[85]
  PIN rw0_rd_out[86]
    DIRECTION OUTPUT ;
    USE SIGNAL ;
    SHAPE ABUTMENT ;
    PORT
      LAYER M3 ;
      RECT 6.255 35.381 6.273 35.435 ;
    END
  END rw0_rd_out[86]
  PIN rw0_rd_out[87]
    DIRECTION OUTPUT ;
    USE SIGNAL ;
    SHAPE ABUTMENT ;
    PORT
      LAYER M3 ;
      RECT 6.543 35.381 6.561 35.435 ;
    END
  END rw0_rd_out[87]
  PIN rw0_rd_out[88]
    DIRECTION OUTPUT ;
    USE SIGNAL ;
    SHAPE ABUTMENT ;
    PORT
      LAYER M3 ;
      RECT 6.831 35.381 6.849 35.435 ;
    END
  END rw0_rd_out[88]
  PIN rw0_rd_out[89]
    DIRECTION OUTPUT ;
    USE SIGNAL ;
    SHAPE ABUTMENT ;
    PORT
      LAYER M3 ;
      RECT 7.119 35.381 7.137 35.435 ;
    END
  END rw0_rd_out[89]
  PIN rw0_rd_out[90]
    DIRECTION OUTPUT ;
    USE SIGNAL ;
    SHAPE ABUTMENT ;
    PORT
      LAYER M3 ;
      RECT 7.407 35.381 7.425 35.435 ;
    END
  END rw0_rd_out[90]
  PIN rw0_rd_out[91]
    DIRECTION OUTPUT ;
    USE SIGNAL ;
    SHAPE ABUTMENT ;
    PORT
      LAYER M3 ;
      RECT 7.695 35.381 7.713 35.435 ;
    END
  END rw0_rd_out[91]
  PIN rw0_rd_out[92]
    DIRECTION OUTPUT ;
    USE SIGNAL ;
    SHAPE ABUTMENT ;
    PORT
      LAYER M3 ;
      RECT 7.983 35.381 8.001 35.435 ;
    END
  END rw0_rd_out[92]
  PIN rw0_rd_out[93]
    DIRECTION OUTPUT ;
    USE SIGNAL ;
    SHAPE ABUTMENT ;
    PORT
      LAYER M3 ;
      RECT 8.271 35.381 8.289 35.435 ;
    END
  END rw0_rd_out[93]
  PIN rw0_rd_out[94]
    DIRECTION OUTPUT ;
    USE SIGNAL ;
    SHAPE ABUTMENT ;
    PORT
      LAYER M3 ;
      RECT 8.559 35.381 8.577 35.435 ;
    END
  END rw0_rd_out[94]
  PIN rw0_rd_out[95]
    DIRECTION OUTPUT ;
    USE SIGNAL ;
    SHAPE ABUTMENT ;
    PORT
      LAYER M3 ;
      RECT 8.847 35.381 8.865 35.435 ;
    END
  END rw0_rd_out[95]
  PIN rw0_rd_out[96]
    DIRECTION OUTPUT ;
    USE SIGNAL ;
    SHAPE ABUTMENT ;
    PORT
      LAYER M3 ;
      RECT 9.135 35.381 9.153 35.435 ;
    END
  END rw0_rd_out[96]
  PIN rw0_rd_out[97]
    DIRECTION OUTPUT ;
    USE SIGNAL ;
    SHAPE ABUTMENT ;
    PORT
      LAYER M3 ;
      RECT 9.423 35.381 9.441 35.435 ;
    END
  END rw0_rd_out[97]
  PIN rw0_rd_out[98]
    DIRECTION OUTPUT ;
    USE SIGNAL ;
    SHAPE ABUTMENT ;
    PORT
      LAYER M3 ;
      RECT 9.711 35.381 9.729 35.435 ;
    END
  END rw0_rd_out[98]
  PIN rw0_rd_out[99]
    DIRECTION OUTPUT ;
    USE SIGNAL ;
    SHAPE ABUTMENT ;
    PORT
      LAYER M3 ;
      RECT 9.999 35.381 10.017 35.435 ;
    END
  END rw0_rd_out[99]
  PIN rw0_rd_out[100]
    DIRECTION OUTPUT ;
    USE SIGNAL ;
    SHAPE ABUTMENT ;
    PORT
      LAYER M3 ;
      RECT 10.287 35.381 10.305 35.435 ;
    END
  END rw0_rd_out[100]
  PIN rw0_rd_out[101]
    DIRECTION OUTPUT ;
    USE SIGNAL ;
    SHAPE ABUTMENT ;
    PORT
      LAYER M3 ;
      RECT 10.575 35.381 10.593 35.435 ;
    END
  END rw0_rd_out[101]
  PIN rw0_rd_out[102]
    DIRECTION OUTPUT ;
    USE SIGNAL ;
    SHAPE ABUTMENT ;
    PORT
      LAYER M3 ;
      RECT 10.863 35.381 10.881 35.435 ;
    END
  END rw0_rd_out[102]
  PIN rw0_rd_out[103]
    DIRECTION OUTPUT ;
    USE SIGNAL ;
    SHAPE ABUTMENT ;
    PORT
      LAYER M3 ;
      RECT 11.151 35.381 11.169 35.435 ;
    END
  END rw0_rd_out[103]
  PIN rw0_rd_out[104]
    DIRECTION OUTPUT ;
    USE SIGNAL ;
    SHAPE ABUTMENT ;
    PORT
      LAYER M3 ;
      RECT 11.439 35.381 11.457 35.435 ;
    END
  END rw0_rd_out[104]
  PIN rw0_rd_out[105]
    DIRECTION OUTPUT ;
    USE SIGNAL ;
    SHAPE ABUTMENT ;
    PORT
      LAYER M3 ;
      RECT 11.727 35.381 11.745 35.435 ;
    END
  END rw0_rd_out[105]
  PIN rw0_rd_out[106]
    DIRECTION OUTPUT ;
    USE SIGNAL ;
    SHAPE ABUTMENT ;
    PORT
      LAYER M3 ;
      RECT 12.015 35.381 12.033 35.435 ;
    END
  END rw0_rd_out[106]
  PIN rw0_rd_out[107]
    DIRECTION OUTPUT ;
    USE SIGNAL ;
    SHAPE ABUTMENT ;
    PORT
      LAYER M3 ;
      RECT 12.303 35.381 12.321 35.435 ;
    END
  END rw0_rd_out[107]
  PIN rw0_rd_out[108]
    DIRECTION OUTPUT ;
    USE SIGNAL ;
    SHAPE ABUTMENT ;
    PORT
      LAYER M3 ;
      RECT 12.591 35.381 12.609 35.435 ;
    END
  END rw0_rd_out[108]
  PIN rw0_rd_out[109]
    DIRECTION OUTPUT ;
    USE SIGNAL ;
    SHAPE ABUTMENT ;
    PORT
      LAYER M3 ;
      RECT 12.879 35.381 12.897 35.435 ;
    END
  END rw0_rd_out[109]
  PIN rw0_rd_out[110]
    DIRECTION OUTPUT ;
    USE SIGNAL ;
    SHAPE ABUTMENT ;
    PORT
      LAYER M3 ;
      RECT 13.167 35.381 13.185 35.435 ;
    END
  END rw0_rd_out[110]
  PIN rw0_rd_out[111]
    DIRECTION OUTPUT ;
    USE SIGNAL ;
    SHAPE ABUTMENT ;
    PORT
      LAYER M3 ;
      RECT 13.455 35.381 13.473 35.435 ;
    END
  END rw0_rd_out[111]
  PIN rw0_rd_out[112]
    DIRECTION OUTPUT ;
    USE SIGNAL ;
    SHAPE ABUTMENT ;
    PORT
      LAYER M3 ;
      RECT 13.743 35.381 13.761 35.435 ;
    END
  END rw0_rd_out[112]
  PIN rw0_rd_out[113]
    DIRECTION OUTPUT ;
    USE SIGNAL ;
    SHAPE ABUTMENT ;
    PORT
      LAYER M3 ;
      RECT 14.031 35.381 14.049 35.435 ;
    END
  END rw0_rd_out[113]
  PIN rw0_rd_out[114]
    DIRECTION OUTPUT ;
    USE SIGNAL ;
    SHAPE ABUTMENT ;
    PORT
      LAYER M3 ;
      RECT 14.319 35.381 14.337 35.435 ;
    END
  END rw0_rd_out[114]
  PIN rw0_rd_out[115]
    DIRECTION OUTPUT ;
    USE SIGNAL ;
    SHAPE ABUTMENT ;
    PORT
      LAYER M3 ;
      RECT 14.607 35.381 14.625 35.435 ;
    END
  END rw0_rd_out[115]
  PIN rw0_rd_out[116]
    DIRECTION OUTPUT ;
    USE SIGNAL ;
    SHAPE ABUTMENT ;
    PORT
      LAYER M3 ;
      RECT 14.895 35.381 14.913 35.435 ;
    END
  END rw0_rd_out[116]
  PIN rw0_rd_out[117]
    DIRECTION OUTPUT ;
    USE SIGNAL ;
    SHAPE ABUTMENT ;
    PORT
      LAYER M3 ;
      RECT 15.183 35.381 15.201 35.435 ;
    END
  END rw0_rd_out[117]
  PIN rw0_rd_out[118]
    DIRECTION OUTPUT ;
    USE SIGNAL ;
    SHAPE ABUTMENT ;
    PORT
      LAYER M3 ;
      RECT 15.471 35.381 15.489 35.435 ;
    END
  END rw0_rd_out[118]
  PIN rw0_rd_out[119]
    DIRECTION OUTPUT ;
    USE SIGNAL ;
    SHAPE ABUTMENT ;
    PORT
      LAYER M3 ;
      RECT 15.759 35.381 15.777 35.435 ;
    END
  END rw0_rd_out[119]
  PIN rw0_rd_out[120]
    DIRECTION OUTPUT ;
    USE SIGNAL ;
    SHAPE ABUTMENT ;
    PORT
      LAYER M3 ;
      RECT 16.047 35.381 16.065 35.435 ;
    END
  END rw0_rd_out[120]
  PIN rw0_rd_out[121]
    DIRECTION OUTPUT ;
    USE SIGNAL ;
    SHAPE ABUTMENT ;
    PORT
      LAYER M3 ;
      RECT 16.335 35.381 16.353 35.435 ;
    END
  END rw0_rd_out[121]
  PIN rw0_rd_out[122]
    DIRECTION OUTPUT ;
    USE SIGNAL ;
    SHAPE ABUTMENT ;
    PORT
      LAYER M3 ;
      RECT 16.623 35.381 16.641 35.435 ;
    END
  END rw0_rd_out[122]
  PIN rw0_rd_out[123]
    DIRECTION OUTPUT ;
    USE SIGNAL ;
    SHAPE ABUTMENT ;
    PORT
      LAYER M3 ;
      RECT 16.911 35.381 16.929 35.435 ;
    END
  END rw0_rd_out[123]
  PIN rw0_rd_out[124]
    DIRECTION OUTPUT ;
    USE SIGNAL ;
    SHAPE ABUTMENT ;
    PORT
      LAYER M3 ;
      RECT 17.199 35.381 17.217 35.435 ;
    END
  END rw0_rd_out[124]
  PIN rw0_rd_out[125]
    DIRECTION OUTPUT ;
    USE SIGNAL ;
    SHAPE ABUTMENT ;
    PORT
      LAYER M3 ;
      RECT 17.487 35.381 17.505 35.435 ;
    END
  END rw0_rd_out[125]
  PIN rw0_rd_out[126]
    DIRECTION OUTPUT ;
    USE SIGNAL ;
    SHAPE ABUTMENT ;
    PORT
      LAYER M3 ;
      RECT 17.775 35.381 17.793 35.435 ;
    END
  END rw0_rd_out[126]
  PIN rw0_rd_out[127]
    DIRECTION OUTPUT ;
    USE SIGNAL ;
    SHAPE ABUTMENT ;
    PORT
      LAYER M3 ;
      RECT 18.063 35.381 18.081 35.435 ;
    END
  END rw0_rd_out[127]
  PIN rw0_rd_out[128]
    DIRECTION OUTPUT ;
    USE SIGNAL ;
    SHAPE ABUTMENT ;
    PORT
      LAYER M3 ;
      RECT 18.351 35.381 18.369 35.435 ;
    END
  END rw0_rd_out[128]
  PIN rw0_rd_out[129]
    DIRECTION OUTPUT ;
    USE SIGNAL ;
    SHAPE ABUTMENT ;
    PORT
      LAYER M3 ;
      RECT 18.639 35.381 18.657 35.435 ;
    END
  END rw0_rd_out[129]
  PIN r0_rd_out[0]
    DIRECTION OUTPUT ;
    USE SIGNAL ;
    SHAPE ABUTMENT ;
    PORT
      LAYER M3 ;
      RECT 28.287 0.000 28.305 0.054 ;
    END
  END r0_rd_out[0]
  PIN r0_rd_out[1]
    DIRECTION OUTPUT ;
    USE SIGNAL ;
    SHAPE ABUTMENT ;
    PORT
      LAYER M3 ;
      RECT 28.503 0.000 28.521 0.054 ;
    END
  END r0_rd_out[1]
  PIN r0_rd_out[2]
    DIRECTION OUTPUT ;
    USE SIGNAL ;
    SHAPE ABUTMENT ;
    PORT
      LAYER M3 ;
      RECT 28.719 0.000 28.737 0.054 ;
    END
  END r0_rd_out[2]
  PIN r0_rd_out[3]
    DIRECTION OUTPUT ;
    USE SIGNAL ;
    SHAPE ABUTMENT ;
    PORT
      LAYER M3 ;
      RECT 28.935 0.000 28.953 0.054 ;
    END
  END r0_rd_out[3]
  PIN r0_rd_out[4]
    DIRECTION OUTPUT ;
    USE SIGNAL ;
    SHAPE ABUTMENT ;
    PORT
      LAYER M3 ;
      RECT 29.151 0.000 29.169 0.054 ;
    END
  END r0_rd_out[4]
  PIN r0_rd_out[5]
    DIRECTION OUTPUT ;
    USE SIGNAL ;
    SHAPE ABUTMENT ;
    PORT
      LAYER M3 ;
      RECT 29.367 0.000 29.385 0.054 ;
    END
  END r0_rd_out[5]
  PIN r0_rd_out[6]
    DIRECTION OUTPUT ;
    USE SIGNAL ;
    SHAPE ABUTMENT ;
    PORT
      LAYER M3 ;
      RECT 29.583 0.000 29.601 0.054 ;
    END
  END r0_rd_out[6]
  PIN r0_rd_out[7]
    DIRECTION OUTPUT ;
    USE SIGNAL ;
    SHAPE ABUTMENT ;
    PORT
      LAYER M3 ;
      RECT 29.799 0.000 29.817 0.054 ;
    END
  END r0_rd_out[7]
  PIN r0_rd_out[8]
    DIRECTION OUTPUT ;
    USE SIGNAL ;
    SHAPE ABUTMENT ;
    PORT
      LAYER M3 ;
      RECT 30.015 0.000 30.033 0.054 ;
    END
  END r0_rd_out[8]
  PIN r0_rd_out[9]
    DIRECTION OUTPUT ;
    USE SIGNAL ;
    SHAPE ABUTMENT ;
    PORT
      LAYER M3 ;
      RECT 30.231 0.000 30.249 0.054 ;
    END
  END r0_rd_out[9]
  PIN r0_rd_out[10]
    DIRECTION OUTPUT ;
    USE SIGNAL ;
    SHAPE ABUTMENT ;
    PORT
      LAYER M3 ;
      RECT 30.447 0.000 30.465 0.054 ;
    END
  END r0_rd_out[10]
  PIN r0_rd_out[11]
    DIRECTION OUTPUT ;
    USE SIGNAL ;
    SHAPE ABUTMENT ;
    PORT
      LAYER M3 ;
      RECT 30.663 0.000 30.681 0.054 ;
    END
  END r0_rd_out[11]
  PIN r0_rd_out[12]
    DIRECTION OUTPUT ;
    USE SIGNAL ;
    SHAPE ABUTMENT ;
    PORT
      LAYER M3 ;
      RECT 30.879 0.000 30.897 0.054 ;
    END
  END r0_rd_out[12]
  PIN r0_rd_out[13]
    DIRECTION OUTPUT ;
    USE SIGNAL ;
    SHAPE ABUTMENT ;
    PORT
      LAYER M3 ;
      RECT 31.095 0.000 31.113 0.054 ;
    END
  END r0_rd_out[13]
  PIN r0_rd_out[14]
    DIRECTION OUTPUT ;
    USE SIGNAL ;
    SHAPE ABUTMENT ;
    PORT
      LAYER M3 ;
      RECT 31.311 0.000 31.329 0.054 ;
    END
  END r0_rd_out[14]
  PIN r0_rd_out[15]
    DIRECTION OUTPUT ;
    USE SIGNAL ;
    SHAPE ABUTMENT ;
    PORT
      LAYER M3 ;
      RECT 31.527 0.000 31.545 0.054 ;
    END
  END r0_rd_out[15]
  PIN r0_rd_out[16]
    DIRECTION OUTPUT ;
    USE SIGNAL ;
    SHAPE ABUTMENT ;
    PORT
      LAYER M3 ;
      RECT 31.743 0.000 31.761 0.054 ;
    END
  END r0_rd_out[16]
  PIN r0_rd_out[17]
    DIRECTION OUTPUT ;
    USE SIGNAL ;
    SHAPE ABUTMENT ;
    PORT
      LAYER M3 ;
      RECT 31.959 0.000 31.977 0.054 ;
    END
  END r0_rd_out[17]
  PIN r0_rd_out[18]
    DIRECTION OUTPUT ;
    USE SIGNAL ;
    SHAPE ABUTMENT ;
    PORT
      LAYER M3 ;
      RECT 32.175 0.000 32.193 0.054 ;
    END
  END r0_rd_out[18]
  PIN r0_rd_out[19]
    DIRECTION OUTPUT ;
    USE SIGNAL ;
    SHAPE ABUTMENT ;
    PORT
      LAYER M3 ;
      RECT 32.391 0.000 32.409 0.054 ;
    END
  END r0_rd_out[19]
  PIN r0_rd_out[20]
    DIRECTION OUTPUT ;
    USE SIGNAL ;
    SHAPE ABUTMENT ;
    PORT
      LAYER M3 ;
      RECT 32.607 0.000 32.625 0.054 ;
    END
  END r0_rd_out[20]
  PIN r0_rd_out[21]
    DIRECTION OUTPUT ;
    USE SIGNAL ;
    SHAPE ABUTMENT ;
    PORT
      LAYER M3 ;
      RECT 32.823 0.000 32.841 0.054 ;
    END
  END r0_rd_out[21]
  PIN r0_rd_out[22]
    DIRECTION OUTPUT ;
    USE SIGNAL ;
    SHAPE ABUTMENT ;
    PORT
      LAYER M3 ;
      RECT 33.039 0.000 33.057 0.054 ;
    END
  END r0_rd_out[22]
  PIN r0_rd_out[23]
    DIRECTION OUTPUT ;
    USE SIGNAL ;
    SHAPE ABUTMENT ;
    PORT
      LAYER M3 ;
      RECT 33.255 0.000 33.273 0.054 ;
    END
  END r0_rd_out[23]
  PIN r0_rd_out[24]
    DIRECTION OUTPUT ;
    USE SIGNAL ;
    SHAPE ABUTMENT ;
    PORT
      LAYER M3 ;
      RECT 33.471 0.000 33.489 0.054 ;
    END
  END r0_rd_out[24]
  PIN r0_rd_out[25]
    DIRECTION OUTPUT ;
    USE SIGNAL ;
    SHAPE ABUTMENT ;
    PORT
      LAYER M3 ;
      RECT 33.687 0.000 33.705 0.054 ;
    END
  END r0_rd_out[25]
  PIN r0_rd_out[26]
    DIRECTION OUTPUT ;
    USE SIGNAL ;
    SHAPE ABUTMENT ;
    PORT
      LAYER M3 ;
      RECT 33.903 0.000 33.921 0.054 ;
    END
  END r0_rd_out[26]
  PIN r0_rd_out[27]
    DIRECTION OUTPUT ;
    USE SIGNAL ;
    SHAPE ABUTMENT ;
    PORT
      LAYER M3 ;
      RECT 34.119 0.000 34.137 0.054 ;
    END
  END r0_rd_out[27]
  PIN r0_rd_out[28]
    DIRECTION OUTPUT ;
    USE SIGNAL ;
    SHAPE ABUTMENT ;
    PORT
      LAYER M3 ;
      RECT 34.335 0.000 34.353 0.054 ;
    END
  END r0_rd_out[28]
  PIN r0_rd_out[29]
    DIRECTION OUTPUT ;
    USE SIGNAL ;
    SHAPE ABUTMENT ;
    PORT
      LAYER M3 ;
      RECT 34.551 0.000 34.569 0.054 ;
    END
  END r0_rd_out[29]
  PIN r0_rd_out[30]
    DIRECTION OUTPUT ;
    USE SIGNAL ;
    SHAPE ABUTMENT ;
    PORT
      LAYER M3 ;
      RECT 34.767 0.000 34.785 0.054 ;
    END
  END r0_rd_out[30]
  PIN r0_rd_out[31]
    DIRECTION OUTPUT ;
    USE SIGNAL ;
    SHAPE ABUTMENT ;
    PORT
      LAYER M3 ;
      RECT 34.983 0.000 35.001 0.054 ;
    END
  END r0_rd_out[31]
  PIN r0_rd_out[32]
    DIRECTION OUTPUT ;
    USE SIGNAL ;
    SHAPE ABUTMENT ;
    PORT
      LAYER M3 ;
      RECT 35.199 0.000 35.217 0.054 ;
    END
  END r0_rd_out[32]
  PIN r0_rd_out[33]
    DIRECTION OUTPUT ;
    USE SIGNAL ;
    SHAPE ABUTMENT ;
    PORT
      LAYER M3 ;
      RECT 35.415 0.000 35.433 0.054 ;
    END
  END r0_rd_out[33]
  PIN r0_rd_out[34]
    DIRECTION OUTPUT ;
    USE SIGNAL ;
    SHAPE ABUTMENT ;
    PORT
      LAYER M3 ;
      RECT 35.631 0.000 35.649 0.054 ;
    END
  END r0_rd_out[34]
  PIN r0_rd_out[35]
    DIRECTION OUTPUT ;
    USE SIGNAL ;
    SHAPE ABUTMENT ;
    PORT
      LAYER M3 ;
      RECT 35.847 0.000 35.865 0.054 ;
    END
  END r0_rd_out[35]
  PIN r0_rd_out[36]
    DIRECTION OUTPUT ;
    USE SIGNAL ;
    SHAPE ABUTMENT ;
    PORT
      LAYER M3 ;
      RECT 36.063 0.000 36.081 0.054 ;
    END
  END r0_rd_out[36]
  PIN r0_rd_out[37]
    DIRECTION OUTPUT ;
    USE SIGNAL ;
    SHAPE ABUTMENT ;
    PORT
      LAYER M3 ;
      RECT 36.279 0.000 36.297 0.054 ;
    END
  END r0_rd_out[37]
  PIN r0_rd_out[38]
    DIRECTION OUTPUT ;
    USE SIGNAL ;
    SHAPE ABUTMENT ;
    PORT
      LAYER M3 ;
      RECT 36.495 0.000 36.513 0.054 ;
    END
  END r0_rd_out[38]
  PIN r0_rd_out[39]
    DIRECTION OUTPUT ;
    USE SIGNAL ;
    SHAPE ABUTMENT ;
    PORT
      LAYER M3 ;
      RECT 36.711 0.000 36.729 0.054 ;
    END
  END r0_rd_out[39]
  PIN r0_rd_out[40]
    DIRECTION OUTPUT ;
    USE SIGNAL ;
    SHAPE ABUTMENT ;
    PORT
      LAYER M3 ;
      RECT 36.927 0.000 36.945 0.054 ;
    END
  END r0_rd_out[40]
  PIN r0_rd_out[41]
    DIRECTION OUTPUT ;
    USE SIGNAL ;
    SHAPE ABUTMENT ;
    PORT
      LAYER M3 ;
      RECT 37.143 0.000 37.161 0.054 ;
    END
  END r0_rd_out[41]
  PIN r0_rd_out[42]
    DIRECTION OUTPUT ;
    USE SIGNAL ;
    SHAPE ABUTMENT ;
    PORT
      LAYER M3 ;
      RECT 37.359 0.000 37.377 0.054 ;
    END
  END r0_rd_out[42]
  PIN r0_rd_out[43]
    DIRECTION OUTPUT ;
    USE SIGNAL ;
    SHAPE ABUTMENT ;
    PORT
      LAYER M3 ;
      RECT 37.575 0.000 37.593 0.054 ;
    END
  END r0_rd_out[43]
  PIN r0_rd_out[44]
    DIRECTION OUTPUT ;
    USE SIGNAL ;
    SHAPE ABUTMENT ;
    PORT
      LAYER M3 ;
      RECT 37.791 0.000 37.809 0.054 ;
    END
  END r0_rd_out[44]
  PIN r0_rd_out[45]
    DIRECTION OUTPUT ;
    USE SIGNAL ;
    SHAPE ABUTMENT ;
    PORT
      LAYER M3 ;
      RECT 38.007 0.000 38.025 0.054 ;
    END
  END r0_rd_out[45]
  PIN r0_rd_out[46]
    DIRECTION OUTPUT ;
    USE SIGNAL ;
    SHAPE ABUTMENT ;
    PORT
      LAYER M3 ;
      RECT 38.223 0.000 38.241 0.054 ;
    END
  END r0_rd_out[46]
  PIN r0_rd_out[47]
    DIRECTION OUTPUT ;
    USE SIGNAL ;
    SHAPE ABUTMENT ;
    PORT
      LAYER M3 ;
      RECT 38.439 0.000 38.457 0.054 ;
    END
  END r0_rd_out[47]
  PIN r0_rd_out[48]
    DIRECTION OUTPUT ;
    USE SIGNAL ;
    SHAPE ABUTMENT ;
    PORT
      LAYER M3 ;
      RECT 38.655 0.000 38.673 0.054 ;
    END
  END r0_rd_out[48]
  PIN r0_rd_out[49]
    DIRECTION OUTPUT ;
    USE SIGNAL ;
    SHAPE ABUTMENT ;
    PORT
      LAYER M3 ;
      RECT 38.871 0.000 38.889 0.054 ;
    END
  END r0_rd_out[49]
  PIN r0_rd_out[50]
    DIRECTION OUTPUT ;
    USE SIGNAL ;
    SHAPE ABUTMENT ;
    PORT
      LAYER M3 ;
      RECT 39.087 0.000 39.105 0.054 ;
    END
  END r0_rd_out[50]
  PIN r0_rd_out[51]
    DIRECTION OUTPUT ;
    USE SIGNAL ;
    SHAPE ABUTMENT ;
    PORT
      LAYER M3 ;
      RECT 39.303 0.000 39.321 0.054 ;
    END
  END r0_rd_out[51]
  PIN r0_rd_out[52]
    DIRECTION OUTPUT ;
    USE SIGNAL ;
    SHAPE ABUTMENT ;
    PORT
      LAYER M3 ;
      RECT 39.519 0.000 39.537 0.054 ;
    END
  END r0_rd_out[52]
  PIN r0_rd_out[53]
    DIRECTION OUTPUT ;
    USE SIGNAL ;
    SHAPE ABUTMENT ;
    PORT
      LAYER M3 ;
      RECT 39.735 0.000 39.753 0.054 ;
    END
  END r0_rd_out[53]
  PIN r0_rd_out[54]
    DIRECTION OUTPUT ;
    USE SIGNAL ;
    SHAPE ABUTMENT ;
    PORT
      LAYER M3 ;
      RECT 39.951 0.000 39.969 0.054 ;
    END
  END r0_rd_out[54]
  PIN r0_rd_out[55]
    DIRECTION OUTPUT ;
    USE SIGNAL ;
    SHAPE ABUTMENT ;
    PORT
      LAYER M3 ;
      RECT 40.167 0.000 40.185 0.054 ;
    END
  END r0_rd_out[55]
  PIN r0_rd_out[56]
    DIRECTION OUTPUT ;
    USE SIGNAL ;
    SHAPE ABUTMENT ;
    PORT
      LAYER M3 ;
      RECT 40.383 0.000 40.401 0.054 ;
    END
  END r0_rd_out[56]
  PIN r0_rd_out[57]
    DIRECTION OUTPUT ;
    USE SIGNAL ;
    SHAPE ABUTMENT ;
    PORT
      LAYER M3 ;
      RECT 40.599 0.000 40.617 0.054 ;
    END
  END r0_rd_out[57]
  PIN r0_rd_out[58]
    DIRECTION OUTPUT ;
    USE SIGNAL ;
    SHAPE ABUTMENT ;
    PORT
      LAYER M3 ;
      RECT 40.815 0.000 40.833 0.054 ;
    END
  END r0_rd_out[58]
  PIN r0_rd_out[59]
    DIRECTION OUTPUT ;
    USE SIGNAL ;
    SHAPE ABUTMENT ;
    PORT
      LAYER M3 ;
      RECT 41.031 0.000 41.049 0.054 ;
    END
  END r0_rd_out[59]
  PIN r0_rd_out[60]
    DIRECTION OUTPUT ;
    USE SIGNAL ;
    SHAPE ABUTMENT ;
    PORT
      LAYER M3 ;
      RECT 41.247 0.000 41.265 0.054 ;
    END
  END r0_rd_out[60]
  PIN r0_rd_out[61]
    DIRECTION OUTPUT ;
    USE SIGNAL ;
    SHAPE ABUTMENT ;
    PORT
      LAYER M3 ;
      RECT 41.463 0.000 41.481 0.054 ;
    END
  END r0_rd_out[61]
  PIN r0_rd_out[62]
    DIRECTION OUTPUT ;
    USE SIGNAL ;
    SHAPE ABUTMENT ;
    PORT
      LAYER M3 ;
      RECT 41.679 0.000 41.697 0.054 ;
    END
  END r0_rd_out[62]
  PIN r0_rd_out[63]
    DIRECTION OUTPUT ;
    USE SIGNAL ;
    SHAPE ABUTMENT ;
    PORT
      LAYER M3 ;
      RECT 41.895 0.000 41.913 0.054 ;
    END
  END r0_rd_out[63]
  PIN r0_rd_out[64]
    DIRECTION OUTPUT ;
    USE SIGNAL ;
    SHAPE ABUTMENT ;
    PORT
      LAYER M3 ;
      RECT 42.111 0.000 42.129 0.054 ;
    END
  END r0_rd_out[64]
  PIN r0_rd_out[65]
    DIRECTION OUTPUT ;
    USE SIGNAL ;
    SHAPE ABUTMENT ;
    PORT
      LAYER M3 ;
      RECT 18.927 35.381 18.945 35.435 ;
    END
  END r0_rd_out[65]
  PIN r0_rd_out[66]
    DIRECTION OUTPUT ;
    USE SIGNAL ;
    SHAPE ABUTMENT ;
    PORT
      LAYER M3 ;
      RECT 19.215 35.381 19.233 35.435 ;
    END
  END r0_rd_out[66]
  PIN r0_rd_out[67]
    DIRECTION OUTPUT ;
    USE SIGNAL ;
    SHAPE ABUTMENT ;
    PORT
      LAYER M3 ;
      RECT 19.503 35.381 19.521 35.435 ;
    END
  END r0_rd_out[67]
  PIN r0_rd_out[68]
    DIRECTION OUTPUT ;
    USE SIGNAL ;
    SHAPE ABUTMENT ;
    PORT
      LAYER M3 ;
      RECT 19.791 35.381 19.809 35.435 ;
    END
  END r0_rd_out[68]
  PIN r0_rd_out[69]
    DIRECTION OUTPUT ;
    USE SIGNAL ;
    SHAPE ABUTMENT ;
    PORT
      LAYER M3 ;
      RECT 20.079 35.381 20.097 35.435 ;
    END
  END r0_rd_out[69]
  PIN r0_rd_out[70]
    DIRECTION OUTPUT ;
    USE SIGNAL ;
    SHAPE ABUTMENT ;
    PORT
      LAYER M3 ;
      RECT 20.367 35.381 20.385 35.435 ;
    END
  END r0_rd_out[70]
  PIN r0_rd_out[71]
    DIRECTION OUTPUT ;
    USE SIGNAL ;
    SHAPE ABUTMENT ;
    PORT
      LAYER M3 ;
      RECT 20.655 35.381 20.673 35.435 ;
    END
  END r0_rd_out[71]
  PIN r0_rd_out[72]
    DIRECTION OUTPUT ;
    USE SIGNAL ;
    SHAPE ABUTMENT ;
    PORT
      LAYER M3 ;
      RECT 20.943 35.381 20.961 35.435 ;
    END
  END r0_rd_out[72]
  PIN r0_rd_out[73]
    DIRECTION OUTPUT ;
    USE SIGNAL ;
    SHAPE ABUTMENT ;
    PORT
      LAYER M3 ;
      RECT 21.231 35.381 21.249 35.435 ;
    END
  END r0_rd_out[73]
  PIN r0_rd_out[74]
    DIRECTION OUTPUT ;
    USE SIGNAL ;
    SHAPE ABUTMENT ;
    PORT
      LAYER M3 ;
      RECT 21.519 35.381 21.537 35.435 ;
    END
  END r0_rd_out[74]
  PIN r0_rd_out[75]
    DIRECTION OUTPUT ;
    USE SIGNAL ;
    SHAPE ABUTMENT ;
    PORT
      LAYER M3 ;
      RECT 21.807 35.381 21.825 35.435 ;
    END
  END r0_rd_out[75]
  PIN r0_rd_out[76]
    DIRECTION OUTPUT ;
    USE SIGNAL ;
    SHAPE ABUTMENT ;
    PORT
      LAYER M3 ;
      RECT 22.095 35.381 22.113 35.435 ;
    END
  END r0_rd_out[76]
  PIN r0_rd_out[77]
    DIRECTION OUTPUT ;
    USE SIGNAL ;
    SHAPE ABUTMENT ;
    PORT
      LAYER M3 ;
      RECT 22.383 35.381 22.401 35.435 ;
    END
  END r0_rd_out[77]
  PIN r0_rd_out[78]
    DIRECTION OUTPUT ;
    USE SIGNAL ;
    SHAPE ABUTMENT ;
    PORT
      LAYER M3 ;
      RECT 22.671 35.381 22.689 35.435 ;
    END
  END r0_rd_out[78]
  PIN r0_rd_out[79]
    DIRECTION OUTPUT ;
    USE SIGNAL ;
    SHAPE ABUTMENT ;
    PORT
      LAYER M3 ;
      RECT 22.959 35.381 22.977 35.435 ;
    END
  END r0_rd_out[79]
  PIN r0_rd_out[80]
    DIRECTION OUTPUT ;
    USE SIGNAL ;
    SHAPE ABUTMENT ;
    PORT
      LAYER M3 ;
      RECT 23.247 35.381 23.265 35.435 ;
    END
  END r0_rd_out[80]
  PIN r0_rd_out[81]
    DIRECTION OUTPUT ;
    USE SIGNAL ;
    SHAPE ABUTMENT ;
    PORT
      LAYER M3 ;
      RECT 23.535 35.381 23.553 35.435 ;
    END
  END r0_rd_out[81]
  PIN r0_rd_out[82]
    DIRECTION OUTPUT ;
    USE SIGNAL ;
    SHAPE ABUTMENT ;
    PORT
      LAYER M3 ;
      RECT 23.823 35.381 23.841 35.435 ;
    END
  END r0_rd_out[82]
  PIN r0_rd_out[83]
    DIRECTION OUTPUT ;
    USE SIGNAL ;
    SHAPE ABUTMENT ;
    PORT
      LAYER M3 ;
      RECT 24.111 35.381 24.129 35.435 ;
    END
  END r0_rd_out[83]
  PIN r0_rd_out[84]
    DIRECTION OUTPUT ;
    USE SIGNAL ;
    SHAPE ABUTMENT ;
    PORT
      LAYER M3 ;
      RECT 24.399 35.381 24.417 35.435 ;
    END
  END r0_rd_out[84]
  PIN r0_rd_out[85]
    DIRECTION OUTPUT ;
    USE SIGNAL ;
    SHAPE ABUTMENT ;
    PORT
      LAYER M3 ;
      RECT 24.687 35.381 24.705 35.435 ;
    END
  END r0_rd_out[85]
  PIN r0_rd_out[86]
    DIRECTION OUTPUT ;
    USE SIGNAL ;
    SHAPE ABUTMENT ;
    PORT
      LAYER M3 ;
      RECT 24.975 35.381 24.993 35.435 ;
    END
  END r0_rd_out[86]
  PIN r0_rd_out[87]
    DIRECTION OUTPUT ;
    USE SIGNAL ;
    SHAPE ABUTMENT ;
    PORT
      LAYER M3 ;
      RECT 25.263 35.381 25.281 35.435 ;
    END
  END r0_rd_out[87]
  PIN r0_rd_out[88]
    DIRECTION OUTPUT ;
    USE SIGNAL ;
    SHAPE ABUTMENT ;
    PORT
      LAYER M3 ;
      RECT 25.551 35.381 25.569 35.435 ;
    END
  END r0_rd_out[88]
  PIN r0_rd_out[89]
    DIRECTION OUTPUT ;
    USE SIGNAL ;
    SHAPE ABUTMENT ;
    PORT
      LAYER M3 ;
      RECT 25.839 35.381 25.857 35.435 ;
    END
  END r0_rd_out[89]
  PIN r0_rd_out[90]
    DIRECTION OUTPUT ;
    USE SIGNAL ;
    SHAPE ABUTMENT ;
    PORT
      LAYER M3 ;
      RECT 26.127 35.381 26.145 35.435 ;
    END
  END r0_rd_out[90]
  PIN r0_rd_out[91]
    DIRECTION OUTPUT ;
    USE SIGNAL ;
    SHAPE ABUTMENT ;
    PORT
      LAYER M3 ;
      RECT 26.415 35.381 26.433 35.435 ;
    END
  END r0_rd_out[91]
  PIN r0_rd_out[92]
    DIRECTION OUTPUT ;
    USE SIGNAL ;
    SHAPE ABUTMENT ;
    PORT
      LAYER M3 ;
      RECT 26.703 35.381 26.721 35.435 ;
    END
  END r0_rd_out[92]
  PIN r0_rd_out[93]
    DIRECTION OUTPUT ;
    USE SIGNAL ;
    SHAPE ABUTMENT ;
    PORT
      LAYER M3 ;
      RECT 26.991 35.381 27.009 35.435 ;
    END
  END r0_rd_out[93]
  PIN r0_rd_out[94]
    DIRECTION OUTPUT ;
    USE SIGNAL ;
    SHAPE ABUTMENT ;
    PORT
      LAYER M3 ;
      RECT 27.279 35.381 27.297 35.435 ;
    END
  END r0_rd_out[94]
  PIN r0_rd_out[95]
    DIRECTION OUTPUT ;
    USE SIGNAL ;
    SHAPE ABUTMENT ;
    PORT
      LAYER M3 ;
      RECT 27.567 35.381 27.585 35.435 ;
    END
  END r0_rd_out[95]
  PIN r0_rd_out[96]
    DIRECTION OUTPUT ;
    USE SIGNAL ;
    SHAPE ABUTMENT ;
    PORT
      LAYER M3 ;
      RECT 27.855 35.381 27.873 35.435 ;
    END
  END r0_rd_out[96]
  PIN r0_rd_out[97]
    DIRECTION OUTPUT ;
    USE SIGNAL ;
    SHAPE ABUTMENT ;
    PORT
      LAYER M3 ;
      RECT 28.143 35.381 28.161 35.435 ;
    END
  END r0_rd_out[97]
  PIN r0_rd_out[98]
    DIRECTION OUTPUT ;
    USE SIGNAL ;
    SHAPE ABUTMENT ;
    PORT
      LAYER M3 ;
      RECT 28.431 35.381 28.449 35.435 ;
    END
  END r0_rd_out[98]
  PIN r0_rd_out[99]
    DIRECTION OUTPUT ;
    USE SIGNAL ;
    SHAPE ABUTMENT ;
    PORT
      LAYER M3 ;
      RECT 28.719 35.381 28.737 35.435 ;
    END
  END r0_rd_out[99]
  PIN r0_rd_out[100]
    DIRECTION OUTPUT ;
    USE SIGNAL ;
    SHAPE ABUTMENT ;
    PORT
      LAYER M3 ;
      RECT 29.007 35.381 29.025 35.435 ;
    END
  END r0_rd_out[100]
  PIN r0_rd_out[101]
    DIRECTION OUTPUT ;
    USE SIGNAL ;
    SHAPE ABUTMENT ;
    PORT
      LAYER M3 ;
      RECT 29.295 35.381 29.313 35.435 ;
    END
  END r0_rd_out[101]
  PIN r0_rd_out[102]
    DIRECTION OUTPUT ;
    USE SIGNAL ;
    SHAPE ABUTMENT ;
    PORT
      LAYER M3 ;
      RECT 29.583 35.381 29.601 35.435 ;
    END
  END r0_rd_out[102]
  PIN r0_rd_out[103]
    DIRECTION OUTPUT ;
    USE SIGNAL ;
    SHAPE ABUTMENT ;
    PORT
      LAYER M3 ;
      RECT 29.871 35.381 29.889 35.435 ;
    END
  END r0_rd_out[103]
  PIN r0_rd_out[104]
    DIRECTION OUTPUT ;
    USE SIGNAL ;
    SHAPE ABUTMENT ;
    PORT
      LAYER M3 ;
      RECT 30.159 35.381 30.177 35.435 ;
    END
  END r0_rd_out[104]
  PIN r0_rd_out[105]
    DIRECTION OUTPUT ;
    USE SIGNAL ;
    SHAPE ABUTMENT ;
    PORT
      LAYER M3 ;
      RECT 30.447 35.381 30.465 35.435 ;
    END
  END r0_rd_out[105]
  PIN r0_rd_out[106]
    DIRECTION OUTPUT ;
    USE SIGNAL ;
    SHAPE ABUTMENT ;
    PORT
      LAYER M3 ;
      RECT 30.735 35.381 30.753 35.435 ;
    END
  END r0_rd_out[106]
  PIN r0_rd_out[107]
    DIRECTION OUTPUT ;
    USE SIGNAL ;
    SHAPE ABUTMENT ;
    PORT
      LAYER M3 ;
      RECT 31.023 35.381 31.041 35.435 ;
    END
  END r0_rd_out[107]
  PIN r0_rd_out[108]
    DIRECTION OUTPUT ;
    USE SIGNAL ;
    SHAPE ABUTMENT ;
    PORT
      LAYER M3 ;
      RECT 31.311 35.381 31.329 35.435 ;
    END
  END r0_rd_out[108]
  PIN r0_rd_out[109]
    DIRECTION OUTPUT ;
    USE SIGNAL ;
    SHAPE ABUTMENT ;
    PORT
      LAYER M3 ;
      RECT 31.599 35.381 31.617 35.435 ;
    END
  END r0_rd_out[109]
  PIN r0_rd_out[110]
    DIRECTION OUTPUT ;
    USE SIGNAL ;
    SHAPE ABUTMENT ;
    PORT
      LAYER M3 ;
      RECT 31.887 35.381 31.905 35.435 ;
    END
  END r0_rd_out[110]
  PIN r0_rd_out[111]
    DIRECTION OUTPUT ;
    USE SIGNAL ;
    SHAPE ABUTMENT ;
    PORT
      LAYER M3 ;
      RECT 32.175 35.381 32.193 35.435 ;
    END
  END r0_rd_out[111]
  PIN r0_rd_out[112]
    DIRECTION OUTPUT ;
    USE SIGNAL ;
    SHAPE ABUTMENT ;
    PORT
      LAYER M3 ;
      RECT 32.463 35.381 32.481 35.435 ;
    END
  END r0_rd_out[112]
  PIN r0_rd_out[113]
    DIRECTION OUTPUT ;
    USE SIGNAL ;
    SHAPE ABUTMENT ;
    PORT
      LAYER M3 ;
      RECT 32.751 35.381 32.769 35.435 ;
    END
  END r0_rd_out[113]
  PIN r0_rd_out[114]
    DIRECTION OUTPUT ;
    USE SIGNAL ;
    SHAPE ABUTMENT ;
    PORT
      LAYER M3 ;
      RECT 33.039 35.381 33.057 35.435 ;
    END
  END r0_rd_out[114]
  PIN r0_rd_out[115]
    DIRECTION OUTPUT ;
    USE SIGNAL ;
    SHAPE ABUTMENT ;
    PORT
      LAYER M3 ;
      RECT 33.327 35.381 33.345 35.435 ;
    END
  END r0_rd_out[115]
  PIN r0_rd_out[116]
    DIRECTION OUTPUT ;
    USE SIGNAL ;
    SHAPE ABUTMENT ;
    PORT
      LAYER M3 ;
      RECT 33.615 35.381 33.633 35.435 ;
    END
  END r0_rd_out[116]
  PIN r0_rd_out[117]
    DIRECTION OUTPUT ;
    USE SIGNAL ;
    SHAPE ABUTMENT ;
    PORT
      LAYER M3 ;
      RECT 33.903 35.381 33.921 35.435 ;
    END
  END r0_rd_out[117]
  PIN r0_rd_out[118]
    DIRECTION OUTPUT ;
    USE SIGNAL ;
    SHAPE ABUTMENT ;
    PORT
      LAYER M3 ;
      RECT 34.191 35.381 34.209 35.435 ;
    END
  END r0_rd_out[118]
  PIN r0_rd_out[119]
    DIRECTION OUTPUT ;
    USE SIGNAL ;
    SHAPE ABUTMENT ;
    PORT
      LAYER M3 ;
      RECT 34.479 35.381 34.497 35.435 ;
    END
  END r0_rd_out[119]
  PIN r0_rd_out[120]
    DIRECTION OUTPUT ;
    USE SIGNAL ;
    SHAPE ABUTMENT ;
    PORT
      LAYER M3 ;
      RECT 34.767 35.381 34.785 35.435 ;
    END
  END r0_rd_out[120]
  PIN r0_rd_out[121]
    DIRECTION OUTPUT ;
    USE SIGNAL ;
    SHAPE ABUTMENT ;
    PORT
      LAYER M3 ;
      RECT 35.055 35.381 35.073 35.435 ;
    END
  END r0_rd_out[121]
  PIN r0_rd_out[122]
    DIRECTION OUTPUT ;
    USE SIGNAL ;
    SHAPE ABUTMENT ;
    PORT
      LAYER M3 ;
      RECT 35.343 35.381 35.361 35.435 ;
    END
  END r0_rd_out[122]
  PIN r0_rd_out[123]
    DIRECTION OUTPUT ;
    USE SIGNAL ;
    SHAPE ABUTMENT ;
    PORT
      LAYER M3 ;
      RECT 35.631 35.381 35.649 35.435 ;
    END
  END r0_rd_out[123]
  PIN r0_rd_out[124]
    DIRECTION OUTPUT ;
    USE SIGNAL ;
    SHAPE ABUTMENT ;
    PORT
      LAYER M3 ;
      RECT 35.919 35.381 35.937 35.435 ;
    END
  END r0_rd_out[124]
  PIN r0_rd_out[125]
    DIRECTION OUTPUT ;
    USE SIGNAL ;
    SHAPE ABUTMENT ;
    PORT
      LAYER M3 ;
      RECT 36.207 35.381 36.225 35.435 ;
    END
  END r0_rd_out[125]
  PIN r0_rd_out[126]
    DIRECTION OUTPUT ;
    USE SIGNAL ;
    SHAPE ABUTMENT ;
    PORT
      LAYER M3 ;
      RECT 36.495 35.381 36.513 35.435 ;
    END
  END r0_rd_out[126]
  PIN r0_rd_out[127]
    DIRECTION OUTPUT ;
    USE SIGNAL ;
    SHAPE ABUTMENT ;
    PORT
      LAYER M3 ;
      RECT 36.783 35.381 36.801 35.435 ;
    END
  END r0_rd_out[127]
  PIN r0_rd_out[128]
    DIRECTION OUTPUT ;
    USE SIGNAL ;
    SHAPE ABUTMENT ;
    PORT
      LAYER M3 ;
      RECT 37.071 35.381 37.089 35.435 ;
    END
  END r0_rd_out[128]
  PIN r0_rd_out[129]
    DIRECTION OUTPUT ;
    USE SIGNAL ;
    SHAPE ABUTMENT ;
    PORT
      LAYER M3 ;
      RECT 37.359 35.381 37.377 35.435 ;
    END
  END r0_rd_out[129]
  PIN rw0_addr_in[0]
    DIRECTION INPUT ;
    USE SIGNAL ;
    SHAPE ABUTMENT ;
    PORT
      LAYER M4 ;
      RECT 0.000 28.788 0.072 28.812 ;
    END
  END rw0_addr_in[0]
  PIN rw0_addr_in[1]
    DIRECTION INPUT ;
    USE SIGNAL ;
    SHAPE ABUTMENT ;
    PORT
      LAYER M4 ;
      RECT 0.000 29.652 0.072 29.676 ;
    END
  END rw0_addr_in[1]
  PIN rw0_addr_in[2]
    DIRECTION INPUT ;
    USE SIGNAL ;
    SHAPE ABUTMENT ;
    PORT
      LAYER M4 ;
      RECT 0.000 30.516 0.072 30.540 ;
    END
  END rw0_addr_in[2]
  PIN rw0_addr_in[3]
    DIRECTION INPUT ;
    USE SIGNAL ;
    SHAPE ABUTMENT ;
    PORT
      LAYER M4 ;
      RECT 0.000 31.380 0.072 31.404 ;
    END
  END rw0_addr_in[3]
  PIN rw0_addr_in[4]
    DIRECTION INPUT ;
    USE SIGNAL ;
    SHAPE ABUTMENT ;
    PORT
      LAYER M4 ;
      RECT 42.891 27.924 42.963 27.948 ;
    END
  END rw0_addr_in[4]
  PIN rw0_addr_in[5]
    DIRECTION INPUT ;
    USE SIGNAL ;
    SHAPE ABUTMENT ;
    PORT
      LAYER M4 ;
      RECT 42.891 28.788 42.963 28.812 ;
    END
  END rw0_addr_in[5]
  PIN rw0_addr_in[6]
    DIRECTION INPUT ;
    USE SIGNAL ;
    SHAPE ABUTMENT ;
    PORT
      LAYER M4 ;
      RECT 42.891 29.652 42.963 29.676 ;
    END
  END rw0_addr_in[6]
  PIN r0_addr_in[0]
    DIRECTION INPUT ;
    USE SIGNAL ;
    SHAPE ABUTMENT ;
    PORT
      LAYER M4 ;
      RECT 0.000 32.244 0.072 32.268 ;
    END
  END r0_addr_in[0]
  PIN r0_addr_in[1]
    DIRECTION INPUT ;
    USE SIGNAL ;
    SHAPE ABUTMENT ;
    PORT
      LAYER M4 ;
      RECT 0.000 33.108 0.072 33.132 ;
    END
  END r0_addr_in[1]
  PIN r0_addr_in[2]
    DIRECTION INPUT ;
    USE SIGNAL ;
    SHAPE ABUTMENT ;
    PORT
      LAYER M4 ;
      RECT 0.000 33.972 0.072 33.996 ;
    END
  END r0_addr_in[2]
  PIN r0_addr_in[3]
    DIRECTION INPUT ;
    USE SIGNAL ;
    SHAPE ABUTMENT ;
    PORT
      LAYER M4 ;
      RECT 0.000 34.836 0.072 34.860 ;
    END
  END r0_addr_in[3]
  PIN r0_addr_in[4]
    DIRECTION INPUT ;
    USE SIGNAL ;
    SHAPE ABUTMENT ;
    PORT
      LAYER M4 ;
      RECT 42.891 30.516 42.963 30.540 ;
    END
  END r0_addr_in[4]
  PIN r0_addr_in[5]
    DIRECTION INPUT ;
    USE SIGNAL ;
    SHAPE ABUTMENT ;
    PORT
      LAYER M4 ;
      RECT 42.891 31.380 42.963 31.404 ;
    END
  END r0_addr_in[5]
  PIN r0_addr_in[6]
    DIRECTION INPUT ;
    USE SIGNAL ;
    SHAPE ABUTMENT ;
    PORT
      LAYER M4 ;
      RECT 42.891 32.244 42.963 32.268 ;
    END
  END r0_addr_in[6]
  PIN rw0_we_in
    DIRECTION INPUT ;
    USE SIGNAL ;
    SHAPE ABUTMENT ;
    PORT
      LAYER M3 ;
      RECT 37.647 35.381 37.665 35.435 ;
    END
  END rw0_we_in
  PIN rw0_ce_in
    DIRECTION INPUT ;
    USE SIGNAL ;
    SHAPE ABUTMENT ;
    PORT
      LAYER M3 ;
      RECT 37.935 35.381 37.953 35.435 ;
    END
  END rw0_ce_in
  PIN rw0_clk
    DIRECTION INPUT ;
    USE SIGNAL ;
    SHAPE ABUTMENT ;
    PORT
      LAYER M3 ;
      RECT 38.223 35.381 38.241 35.435 ;
    END
  END rw0_clk
  PIN r0_ce_in
    DIRECTION INPUT ;
    USE SIGNAL ;
    SHAPE ABUTMENT ;
    PORT
      LAYER M3 ;
      RECT 38.511 35.381 38.529 35.435 ;
    END
  END r0_ce_in
  PIN r0_clk
    DIRECTION INPUT ;
    USE SIGNAL ;
    SHAPE ABUTMENT ;
    PORT
      LAYER M3 ;
      RECT 38.799 35.381 38.817 35.435 ;
    END
  END r0_clk
  PIN VSS
    DIRECTION INOUT ;
    USE GROUND ;
    PORT
      LAYER M4 ;
      RECT 0.216 0.240 42.747 0.336 ;
      RECT 0.216 1.008 42.747 1.104 ;
      RECT 0.216 1.776 42.747 1.872 ;
      RECT 0.216 2.544 42.747 2.640 ;
      RECT 0.216 3.312 42.747 3.408 ;
      RECT 0.216 4.080 42.747 4.176 ;
      RECT 0.216 4.848 42.747 4.944 ;
      RECT 0.216 5.616 42.747 5.712 ;
      RECT 0.216 6.384 42.747 6.480 ;
      RECT 0.216 7.152 42.747 7.248 ;
      RECT 0.216 7.920 42.747 8.016 ;
      RECT 0.216 8.688 42.747 8.784 ;
      RECT 0.216 9.456 42.747 9.552 ;
      RECT 0.216 10.224 42.747 10.320 ;
      RECT 0.216 10.992 42.747 11.088 ;
      RECT 0.216 11.760 42.747 11.856 ;
      RECT 0.216 12.528 42.747 12.624 ;
      RECT 0.216 13.296 42.747 13.392 ;
      RECT 0.216 14.064 42.747 14.160 ;
      RECT 0.216 14.832 42.747 14.928 ;
      RECT 0.216 15.600 42.747 15.696 ;
      RECT 0.216 16.368 42.747 16.464 ;
      RECT 0.216 17.136 42.747 17.232 ;
      RECT 0.216 17.904 42.747 18.000 ;
      RECT 0.216 18.672 42.747 18.768 ;
      RECT 0.216 19.440 42.747 19.536 ;
      RECT 0.216 20.208 42.747 20.304 ;
      RECT 0.216 20.976 42.747 21.072 ;
      RECT 0.216 21.744 42.747 21.840 ;
      RECT 0.216 22.512 42.747 22.608 ;
      RECT 0.216 23.280 42.747 23.376 ;
      RECT 0.216 24.048 42.747 24.144 ;
      RECT 0.216 24.816 42.747 24.912 ;
      RECT 0.216 25.584 42.747 25.680 ;
      RECT 0.216 26.352 42.747 26.448 ;
      RECT 0.216 27.120 42.747 27.216 ;
      RECT 0.216 27.888 42.747 27.984 ;
      RECT 0.216 28.656 42.747 28.752 ;
      RECT 0.216 29.424 42.747 29.520 ;
      RECT 0.216 30.192 42.747 30.288 ;
      RECT 0.216 30.960 42.747 31.056 ;
      RECT 0.216 31.728 42.747 31.824 ;
      RECT 0.216 32.496 42.747 32.592 ;
      RECT 0.216 33.264 42.747 33.360 ;
      RECT 0.216 34.032 42.747 34.128 ;
      RECT 0.216 34.800 42.747 34.896 ;
    END
  END VSS
  PIN VDD
    DIRECTION INOUT ;
    USE POWER ;
    PORT
      LAYER M4 ;
      RECT 0.216 0.240 42.747 0.336 ;
      RECT 0.216 1.008 42.747 1.104 ;
      RECT 0.216 1.776 42.747 1.872 ;
      RECT 0.216 2.544 42.747 2.640 ;
      RECT 0.216 3.312 42.747 3.408 ;
      RECT 0.216 4.080 42.747 4.176 ;
      RECT 0.216 4.848 42.747 4.944 ;
      RECT 0.216 5.616 42.747 5.712 ;
      RECT 0.216 6.384 42.747 6.480 ;
      RECT 0.216 7.152 42.747 7.248 ;
      RECT 0.216 7.920 42.747 8.016 ;
      RECT 0.216 8.688 42.747 8.784 ;
      RECT 0.216 9.456 42.747 9.552 ;
      RECT 0.216 10.224 42.747 10.320 ;
      RECT 0.216 10.992 42.747 11.088 ;
      RECT 0.216 11.760 42.747 11.856 ;
      RECT 0.216 12.528 42.747 12.624 ;
      RECT 0.216 13.296 42.747 13.392 ;
      RECT 0.216 14.064 42.747 14.160 ;
      RECT 0.216 14.832 42.747 14.928 ;
      RECT 0.216 15.600 42.747 15.696 ;
      RECT 0.216 16.368 42.747 16.464 ;
      RECT 0.216 17.136 42.747 17.232 ;
      RECT 0.216 17.904 42.747 18.000 ;
      RECT 0.216 18.672 42.747 18.768 ;
      RECT 0.216 19.440 42.747 19.536 ;
      RECT 0.216 20.208 42.747 20.304 ;
      RECT 0.216 20.976 42.747 21.072 ;
      RECT 0.216 21.744 42.747 21.840 ;
      RECT 0.216 22.512 42.747 22.608 ;
      RECT 0.216 23.280 42.747 23.376 ;
      RECT 0.216 24.048 42.747 24.144 ;
      RECT 0.216 24.816 42.747 24.912 ;
      RECT 0.216 25.584 42.747 25.680 ;
      RECT 0.216 26.352 42.747 26.448 ;
      RECT 0.216 27.120 42.747 27.216 ;
      RECT 0.216 27.888 42.747 27.984 ;
      RECT 0.216 28.656 42.747 28.752 ;
      RECT 0.216 29.424 42.747 29.520 ;
      RECT 0.216 30.192 42.747 30.288 ;
      RECT 0.216 30.960 42.747 31.056 ;
      RECT 0.216 31.728 42.747 31.824 ;
      RECT 0.216 32.496 42.747 32.592 ;
      RECT 0.216 33.264 42.747 33.360 ;
      RECT 0.216 34.032 42.747 34.128 ;
      RECT 0.216 34.800 42.747 34.896 ;
    END
  END VDD
  OBS
    LAYER M1 ;
    RECT 0 0 42.963 35.435 ;
    LAYER M2 ;
    RECT 0 0 42.963 35.435 ;
    LAYER M3 ;
    RECT 0 0 42.963 35.435 ;
    LAYER M4 ;
    RECT 0 0 42.963 35.435 ;
  END
END fakeram_1rw1r_130w128d_sram

END LIBRARY
